VERSION 5.8 ;
BUSBITCHARS "[]" ;
DIVIDERCHAR "/" ;
UNITS
    DATABASE MICRONS 1000 ;
END UNITS

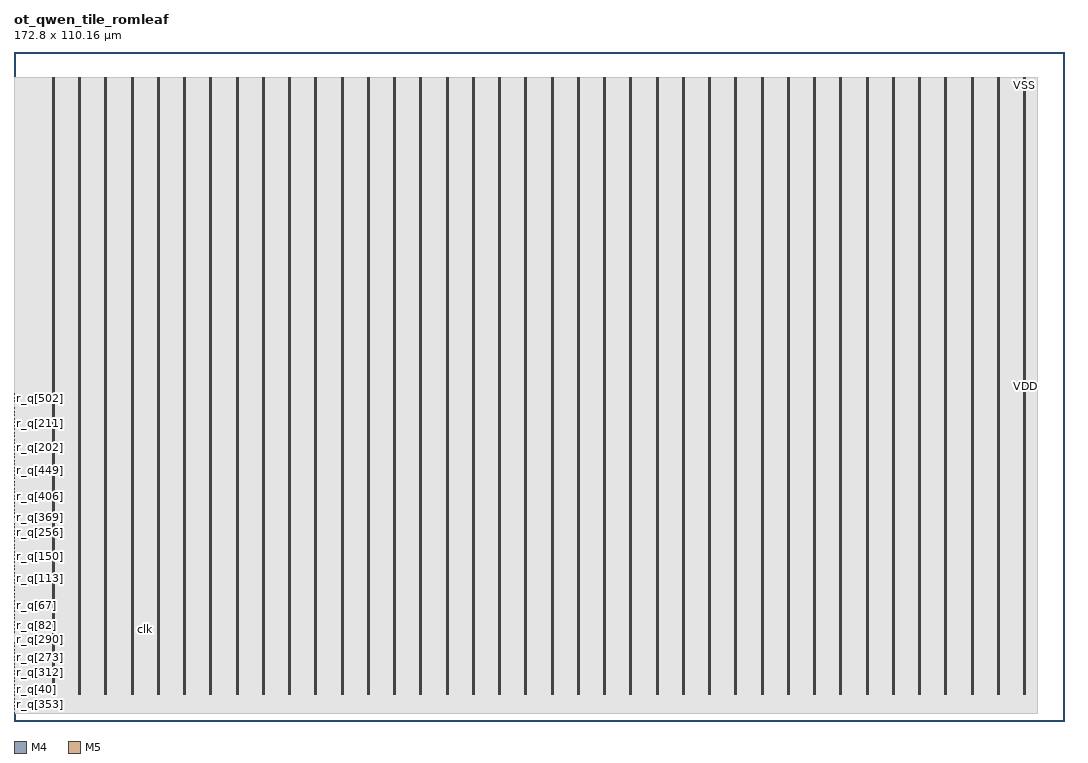
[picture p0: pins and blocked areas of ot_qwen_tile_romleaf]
MACRO ot_qwen_tile_romleaf
  FOREIGN ot_qwen_tile_romleaf 0 0 ;
  CLASS BLOCK ;
  SIZE 172.8 BY 110.16 ;
  PIN ad_d[0]
    DIRECTION INPUT ;
    USE SIGNAL ;
    PORT
      LAYER M4 ;
        RECT  0 20.4 0.084 20.424 ;
    END
  END ad_d[0]
  PIN ad_d[10]
    DIRECTION INPUT ;
    USE SIGNAL ;
    PORT
      LAYER M4 ;
        RECT  0 21.36 0.084 21.384 ;
    END
  END ad_d[10]
  PIN ad_d[11]
    DIRECTION INPUT ;
    USE SIGNAL ;
    PORT
      LAYER M4 ;
        RECT  0 21.456 0.084 21.48 ;
    END
  END ad_d[11]
  PIN ad_d[1]
    DIRECTION INPUT ;
    USE SIGNAL ;
    PORT
      LAYER M4 ;
        RECT  0 20.496 0.084 20.52 ;
    END
  END ad_d[1]
  PIN ad_d[2]
    DIRECTION INPUT ;
    USE SIGNAL ;
    PORT
      LAYER M4 ;
        RECT  0 20.592 0.084 20.616 ;
    END
  END ad_d[2]
  PIN ad_d[3]
    DIRECTION INPUT ;
    USE SIGNAL ;
    PORT
      LAYER M4 ;
        RECT  0 20.688 0.084 20.712 ;
    END
  END ad_d[3]
  PIN ad_d[4]
    DIRECTION INPUT ;
    USE SIGNAL ;
    PORT
      LAYER M4 ;
        RECT  0 20.784 0.084 20.808 ;
    END
  END ad_d[4]
  PIN ad_d[5]
    DIRECTION INPUT ;
    USE SIGNAL ;
    PORT
      LAYER M4 ;
        RECT  0 20.88 0.084 20.904 ;
    END
  END ad_d[5]
  PIN ad_d[6]
    DIRECTION INPUT ;
    USE SIGNAL ;
    PORT
      LAYER M4 ;
        RECT  0 20.976 0.084 21 ;
    END
  END ad_d[6]
  PIN ad_d[7]
    DIRECTION INPUT ;
    USE SIGNAL ;
    PORT
      LAYER M4 ;
        RECT  0 21.072 0.084 21.096 ;
    END
  END ad_d[7]
  PIN ad_d[8]
    DIRECTION INPUT ;
    USE SIGNAL ;
    PORT
      LAYER M4 ;
        RECT  0 21.168 0.084 21.192 ;
    END
  END ad_d[8]
  PIN ad_d[9]
    DIRECTION INPUT ;
    USE SIGNAL ;
    PORT
      LAYER M4 ;
        RECT  0 21.264 0.084 21.288 ;
    END
  END ad_d[9]
  PIN any_d
    DIRECTION INPUT ;
    USE SIGNAL ;
    PORT
      LAYER M4 ;
        RECT  0 21.552 0.084 21.576 ;
    END
  END any_d
  PIN ce_d
    DIRECTION INPUT ;
    USE SIGNAL ;
    PORT
      LAYER M4 ;
        RECT  0 21.648 0.084 21.672 ;
    END
  END ce_d
  PIN clk
    DIRECTION INPUT ;
    USE SIGNAL ;
    PORT
      LAYER M5 ;
        RECT  21.588 14.88 21.636 15.36 ;
    END
  END clk
  PIN r_q[0]
    DIRECTION OUTPUT ;
    USE SIGNAL ;
    PORT
      LAYER M4 ;
        RECT  0 21.84 0.084 21.864 ;
    END
  END r_q[0]
  PIN r_q[100]
    DIRECTION OUTPUT ;
    USE SIGNAL ;
    PORT
      LAYER M4 ;
        RECT  0 16.08 0.084 16.104 ;
    END
  END r_q[100]
  PIN r_q[101]
    DIRECTION OUTPUT ;
    USE SIGNAL ;
    PORT
      LAYER M4 ;
        RECT  0 16.176 0.084 16.2 ;
    END
  END r_q[101]
  PIN r_q[102]
    DIRECTION OUTPUT ;
    USE SIGNAL ;
    PORT
      LAYER M4 ;
        RECT  0 16.272 0.084 16.296 ;
    END
  END r_q[102]
  PIN r_q[103]
    DIRECTION OUTPUT ;
    USE SIGNAL ;
    PORT
      LAYER M4 ;
        RECT  0 16.368 0.084 16.392 ;
    END
  END r_q[103]
  PIN r_q[104]
    DIRECTION OUTPUT ;
    USE SIGNAL ;
    PORT
      LAYER M4 ;
        RECT  0 16.464 0.084 16.488 ;
    END
  END r_q[104]
  PIN r_q[105]
    DIRECTION OUTPUT ;
    USE SIGNAL ;
    PORT
      LAYER M4 ;
        RECT  0 16.56 0.084 16.584 ;
    END
  END r_q[105]
  PIN r_q[106]
    DIRECTION OUTPUT ;
    USE SIGNAL ;
    PORT
      LAYER M4 ;
        RECT  0 16.656 0.084 16.68 ;
    END
  END r_q[106]
  PIN r_q[107]
    DIRECTION OUTPUT ;
    USE SIGNAL ;
    PORT
      LAYER M4 ;
        RECT  0 16.752 0.084 16.776 ;
    END
  END r_q[107]
  PIN r_q[108]
    DIRECTION OUTPUT ;
    USE SIGNAL ;
    PORT
      LAYER M4 ;
        RECT  0 16.848 0.084 16.872 ;
    END
  END r_q[108]
  PIN r_q[109]
    DIRECTION OUTPUT ;
    USE SIGNAL ;
    PORT
      LAYER M4 ;
        RECT  0 16.944 0.084 16.968 ;
    END
  END r_q[109]
  PIN r_q[10]
    DIRECTION OUTPUT ;
    USE SIGNAL ;
    PORT
      LAYER M4 ;
        RECT  0 22.8 0.084 22.824 ;
    END
  END r_q[10]
  PIN r_q[110]
    DIRECTION OUTPUT ;
    USE SIGNAL ;
    PORT
      LAYER M4 ;
        RECT  0 17.04 0.084 17.064 ;
    END
  END r_q[110]
  PIN r_q[111]
    DIRECTION OUTPUT ;
    USE SIGNAL ;
    PORT
      LAYER M4 ;
        RECT  0 17.136 0.084 17.16 ;
    END
  END r_q[111]
  PIN r_q[112]
    DIRECTION OUTPUT ;
    USE SIGNAL ;
    PORT
      LAYER M4 ;
        RECT  0 17.232 0.084 17.256 ;
    END
  END r_q[112]
  PIN r_q[113]
    DIRECTION OUTPUT ;
    USE SIGNAL ;
    PORT
      LAYER M4 ;
        RECT  0 23.472 0.084 23.496 ;
    END
  END r_q[113]
  PIN r_q[114]
    DIRECTION OUTPUT ;
    USE SIGNAL ;
    PORT
      LAYER M4 ;
        RECT  0 23.568 0.084 23.592 ;
    END
  END r_q[114]
  PIN r_q[115]
    DIRECTION OUTPUT ;
    USE SIGNAL ;
    PORT
      LAYER M4 ;
        RECT  0 23.664 0.084 23.688 ;
    END
  END r_q[115]
  PIN r_q[116]
    DIRECTION OUTPUT ;
    USE SIGNAL ;
    PORT
      LAYER M4 ;
        RECT  0 23.76 0.084 23.784 ;
    END
  END r_q[116]
  PIN r_q[117]
    DIRECTION OUTPUT ;
    USE SIGNAL ;
    PORT
      LAYER M4 ;
        RECT  0 23.856 0.084 23.88 ;
    END
  END r_q[117]
  PIN r_q[118]
    DIRECTION OUTPUT ;
    USE SIGNAL ;
    PORT
      LAYER M4 ;
        RECT  0 23.952 0.084 23.976 ;
    END
  END r_q[118]
  PIN r_q[119]
    DIRECTION OUTPUT ;
    USE SIGNAL ;
    PORT
      LAYER M4 ;
        RECT  0 24.048 0.084 24.072 ;
    END
  END r_q[119]
  PIN r_q[11]
    DIRECTION OUTPUT ;
    USE SIGNAL ;
    PORT
      LAYER M4 ;
        RECT  0 22.896 0.084 22.92 ;
    END
  END r_q[11]
  PIN r_q[120]
    DIRECTION OUTPUT ;
    USE SIGNAL ;
    PORT
      LAYER M4 ;
        RECT  0 24.144 0.084 24.168 ;
    END
  END r_q[120]
  PIN r_q[121]
    DIRECTION OUTPUT ;
    USE SIGNAL ;
    PORT
      LAYER M4 ;
        RECT  0 24.24 0.084 24.264 ;
    END
  END r_q[121]
  PIN r_q[122]
    DIRECTION OUTPUT ;
    USE SIGNAL ;
    PORT
      LAYER M4 ;
        RECT  0 24.336 0.084 24.36 ;
    END
  END r_q[122]
  PIN r_q[123]
    DIRECTION OUTPUT ;
    USE SIGNAL ;
    PORT
      LAYER M4 ;
        RECT  0 24.432 0.084 24.456 ;
    END
  END r_q[123]
  PIN r_q[124]
    DIRECTION OUTPUT ;
    USE SIGNAL ;
    PORT
      LAYER M4 ;
        RECT  0 24.528 0.084 24.552 ;
    END
  END r_q[124]
  PIN r_q[125]
    DIRECTION OUTPUT ;
    USE SIGNAL ;
    PORT
      LAYER M4 ;
        RECT  0 24.624 0.084 24.648 ;
    END
  END r_q[125]
  PIN r_q[126]
    DIRECTION OUTPUT ;
    USE SIGNAL ;
    PORT
      LAYER M4 ;
        RECT  0 24.72 0.084 24.744 ;
    END
  END r_q[126]
  PIN r_q[127]
    DIRECTION OUTPUT ;
    USE SIGNAL ;
    PORT
      LAYER M4 ;
        RECT  0 24.816 0.084 24.84 ;
    END
  END r_q[127]
  PIN r_q[128]
    DIRECTION OUTPUT ;
    USE SIGNAL ;
    PORT
      LAYER M4 ;
        RECT  0 24.912 0.084 24.936 ;
    END
  END r_q[128]
  PIN r_q[129]
    DIRECTION OUTPUT ;
    USE SIGNAL ;
    PORT
      LAYER M4 ;
        RECT  0 25.008 0.084 25.032 ;
    END
  END r_q[129]
  PIN r_q[12]
    DIRECTION OUTPUT ;
    USE SIGNAL ;
    PORT
      LAYER M4 ;
        RECT  0 22.992 0.084 23.016 ;
    END
  END r_q[12]
  PIN r_q[130]
    DIRECTION OUTPUT ;
    USE SIGNAL ;
    PORT
      LAYER M4 ;
        RECT  0 25.104 0.084 25.128 ;
    END
  END r_q[130]
  PIN r_q[131]
    DIRECTION OUTPUT ;
    USE SIGNAL ;
    PORT
      LAYER M4 ;
        RECT  0 25.2 0.084 25.224 ;
    END
  END r_q[131]
  PIN r_q[132]
    DIRECTION OUTPUT ;
    USE SIGNAL ;
    PORT
      LAYER M4 ;
        RECT  0 25.296 0.084 25.32 ;
    END
  END r_q[132]
  PIN r_q[133]
    DIRECTION OUTPUT ;
    USE SIGNAL ;
    PORT
      LAYER M4 ;
        RECT  0 25.392 0.084 25.416 ;
    END
  END r_q[133]
  PIN r_q[134]
    DIRECTION OUTPUT ;
    USE SIGNAL ;
    PORT
      LAYER M4 ;
        RECT  0 25.488 0.084 25.512 ;
    END
  END r_q[134]
  PIN r_q[135]
    DIRECTION OUTPUT ;
    USE SIGNAL ;
    PORT
      LAYER M4 ;
        RECT  0 25.584 0.084 25.608 ;
    END
  END r_q[135]
  PIN r_q[136]
    DIRECTION OUTPUT ;
    USE SIGNAL ;
    PORT
      LAYER M4 ;
        RECT  0 25.68 0.084 25.704 ;
    END
  END r_q[136]
  PIN r_q[137]
    DIRECTION OUTPUT ;
    USE SIGNAL ;
    PORT
      LAYER M4 ;
        RECT  0 25.776 0.084 25.8 ;
    END
  END r_q[137]
  PIN r_q[138]
    DIRECTION OUTPUT ;
    USE SIGNAL ;
    PORT
      LAYER M4 ;
        RECT  0 25.872 0.084 25.896 ;
    END
  END r_q[138]
  PIN r_q[139]
    DIRECTION OUTPUT ;
    USE SIGNAL ;
    PORT
      LAYER M4 ;
        RECT  0 25.968 0.084 25.992 ;
    END
  END r_q[139]
  PIN r_q[13]
    DIRECTION OUTPUT ;
    USE SIGNAL ;
    PORT
      LAYER M4 ;
        RECT  0 23.088 0.084 23.112 ;
    END
  END r_q[13]
  PIN r_q[140]
    DIRECTION OUTPUT ;
    USE SIGNAL ;
    PORT
      LAYER M4 ;
        RECT  0 26.064 0.084 26.088 ;
    END
  END r_q[140]
  PIN r_q[141]
    DIRECTION OUTPUT ;
    USE SIGNAL ;
    PORT
      LAYER M4 ;
        RECT  0 26.16 0.084 26.184 ;
    END
  END r_q[141]
  PIN r_q[142]
    DIRECTION OUTPUT ;
    USE SIGNAL ;
    PORT
      LAYER M4 ;
        RECT  0 26.256 0.084 26.28 ;
    END
  END r_q[142]
  PIN r_q[143]
    DIRECTION OUTPUT ;
    USE SIGNAL ;
    PORT
      LAYER M4 ;
        RECT  0 26.352 0.084 26.376 ;
    END
  END r_q[143]
  PIN r_q[144]
    DIRECTION OUTPUT ;
    USE SIGNAL ;
    PORT
      LAYER M4 ;
        RECT  0 26.448 0.084 26.472 ;
    END
  END r_q[144]
  PIN r_q[145]
    DIRECTION OUTPUT ;
    USE SIGNAL ;
    PORT
      LAYER M4 ;
        RECT  0 26.544 0.084 26.568 ;
    END
  END r_q[145]
  PIN r_q[146]
    DIRECTION OUTPUT ;
    USE SIGNAL ;
    PORT
      LAYER M4 ;
        RECT  0 26.64 0.084 26.664 ;
    END
  END r_q[146]
  PIN r_q[147]
    DIRECTION OUTPUT ;
    USE SIGNAL ;
    PORT
      LAYER M4 ;
        RECT  0 26.736 0.084 26.76 ;
    END
  END r_q[147]
  PIN r_q[148]
    DIRECTION OUTPUT ;
    USE SIGNAL ;
    PORT
      LAYER M4 ;
        RECT  0 26.832 0.084 26.856 ;
    END
  END r_q[148]
  PIN r_q[149]
    DIRECTION OUTPUT ;
    USE SIGNAL ;
    PORT
      LAYER M4 ;
        RECT  0 26.928 0.084 26.952 ;
    END
  END r_q[149]
  PIN r_q[14]
    DIRECTION OUTPUT ;
    USE SIGNAL ;
    PORT
      LAYER M4 ;
        RECT  0 23.184 0.084 23.208 ;
    END
  END r_q[14]
  PIN r_q[150]
    DIRECTION OUTPUT ;
    USE SIGNAL ;
    PORT
      LAYER M4 ;
        RECT  0 27.024 0.084 27.048 ;
    END
  END r_q[150]
  PIN r_q[151]
    DIRECTION OUTPUT ;
    USE SIGNAL ;
    PORT
      LAYER M4 ;
        RECT  0 27.12 0.084 27.144 ;
    END
  END r_q[151]
  PIN r_q[152]
    DIRECTION OUTPUT ;
    USE SIGNAL ;
    PORT
      LAYER M4 ;
        RECT  0 27.216 0.084 27.24 ;
    END
  END r_q[152]
  PIN r_q[153]
    DIRECTION OUTPUT ;
    USE SIGNAL ;
    PORT
      LAYER M4 ;
        RECT  0 27.312 0.084 27.336 ;
    END
  END r_q[153]
  PIN r_q[154]
    DIRECTION OUTPUT ;
    USE SIGNAL ;
    PORT
      LAYER M4 ;
        RECT  0 27.408 0.084 27.432 ;
    END
  END r_q[154]
  PIN r_q[155]
    DIRECTION OUTPUT ;
    USE SIGNAL ;
    PORT
      LAYER M4 ;
        RECT  0 27.504 0.084 27.528 ;
    END
  END r_q[155]
  PIN r_q[156]
    DIRECTION OUTPUT ;
    USE SIGNAL ;
    PORT
      LAYER M4 ;
        RECT  0 27.6 0.084 27.624 ;
    END
  END r_q[156]
  PIN r_q[157]
    DIRECTION OUTPUT ;
    USE SIGNAL ;
    PORT
      LAYER M4 ;
        RECT  0 27.696 0.084 27.72 ;
    END
  END r_q[157]
  PIN r_q[158]
    DIRECTION OUTPUT ;
    USE SIGNAL ;
    PORT
      LAYER M4 ;
        RECT  0 27.792 0.084 27.816 ;
    END
  END r_q[158]
  PIN r_q[159]
    DIRECTION OUTPUT ;
    USE SIGNAL ;
    PORT
      LAYER M4 ;
        RECT  0 27.888 0.084 27.912 ;
    END
  END r_q[159]
  PIN r_q[15]
    DIRECTION OUTPUT ;
    USE SIGNAL ;
    PORT
      LAYER M4 ;
        RECT  0 23.28 0.084 23.304 ;
    END
  END r_q[15]
  PIN r_q[160]
    DIRECTION OUTPUT ;
    USE SIGNAL ;
    PORT
      LAYER M4 ;
        RECT  0 27.984 0.084 28.008 ;
    END
  END r_q[160]
  PIN r_q[161]
    DIRECTION OUTPUT ;
    USE SIGNAL ;
    PORT
      LAYER M4 ;
        RECT  0 28.08 0.084 28.104 ;
    END
  END r_q[161]
  PIN r_q[162]
    DIRECTION OUTPUT ;
    USE SIGNAL ;
    PORT
      LAYER M4 ;
        RECT  0 28.176 0.084 28.2 ;
    END
  END r_q[162]
  PIN r_q[163]
    DIRECTION OUTPUT ;
    USE SIGNAL ;
    PORT
      LAYER M4 ;
        RECT  0 28.272 0.084 28.296 ;
    END
  END r_q[163]
  PIN r_q[164]
    DIRECTION OUTPUT ;
    USE SIGNAL ;
    PORT
      LAYER M4 ;
        RECT  0 28.368 0.084 28.392 ;
    END
  END r_q[164]
  PIN r_q[165]
    DIRECTION OUTPUT ;
    USE SIGNAL ;
    PORT
      LAYER M4 ;
        RECT  0 28.464 0.084 28.488 ;
    END
  END r_q[165]
  PIN r_q[166]
    DIRECTION OUTPUT ;
    USE SIGNAL ;
    PORT
      LAYER M4 ;
        RECT  0 28.56 0.084 28.584 ;
    END
  END r_q[166]
  PIN r_q[167]
    DIRECTION OUTPUT ;
    USE SIGNAL ;
    PORT
      LAYER M4 ;
        RECT  0 28.656 0.084 28.68 ;
    END
  END r_q[167]
  PIN r_q[168]
    DIRECTION OUTPUT ;
    USE SIGNAL ;
    PORT
      LAYER M4 ;
        RECT  0 28.752 0.084 28.776 ;
    END
  END r_q[168]
  PIN r_q[169]
    DIRECTION OUTPUT ;
    USE SIGNAL ;
    PORT
      LAYER M4 ;
        RECT  0 28.848 0.084 28.872 ;
    END
  END r_q[169]
  PIN r_q[16]
    DIRECTION OUTPUT ;
    USE SIGNAL ;
    PORT
      LAYER M4 ;
        RECT  0 23.376 0.084 23.4 ;
    END
  END r_q[16]
  PIN r_q[170]
    DIRECTION OUTPUT ;
    USE SIGNAL ;
    PORT
      LAYER M4 ;
        RECT  0 28.944 0.084 28.968 ;
    END
  END r_q[170]
  PIN r_q[171]
    DIRECTION OUTPUT ;
    USE SIGNAL ;
    PORT
      LAYER M4 ;
        RECT  0 29.04 0.084 29.064 ;
    END
  END r_q[171]
  PIN r_q[172]
    DIRECTION OUTPUT ;
    USE SIGNAL ;
    PORT
      LAYER M4 ;
        RECT  0 29.136 0.084 29.16 ;
    END
  END r_q[172]
  PIN r_q[173]
    DIRECTION OUTPUT ;
    USE SIGNAL ;
    PORT
      LAYER M4 ;
        RECT  0 29.232 0.084 29.256 ;
    END
  END r_q[173]
  PIN r_q[174]
    DIRECTION OUTPUT ;
    USE SIGNAL ;
    PORT
      LAYER M4 ;
        RECT  0 29.328 0.084 29.352 ;
    END
  END r_q[174]
  PIN r_q[175]
    DIRECTION OUTPUT ;
    USE SIGNAL ;
    PORT
      LAYER M4 ;
        RECT  0 29.424 0.084 29.448 ;
    END
  END r_q[175]
  PIN r_q[176]
    DIRECTION OUTPUT ;
    USE SIGNAL ;
    PORT
      LAYER M4 ;
        RECT  0 29.52 0.084 29.544 ;
    END
  END r_q[176]
  PIN r_q[177]
    DIRECTION OUTPUT ;
    USE SIGNAL ;
    PORT
      LAYER M4 ;
        RECT  0 42.672 0.084 42.696 ;
    END
  END r_q[177]
  PIN r_q[178]
    DIRECTION OUTPUT ;
    USE SIGNAL ;
    PORT
      LAYER M4 ;
        RECT  0 42.768 0.084 42.792 ;
    END
  END r_q[178]
  PIN r_q[179]
    DIRECTION OUTPUT ;
    USE SIGNAL ;
    PORT
      LAYER M4 ;
        RECT  0 42.864 0.084 42.888 ;
    END
  END r_q[179]
  PIN r_q[17]
    DIRECTION OUTPUT ;
    USE SIGNAL ;
    PORT
      LAYER M4 ;
        RECT  0 4.272 0.084 4.296 ;
    END
  END r_q[17]
  PIN r_q[180]
    DIRECTION OUTPUT ;
    USE SIGNAL ;
    PORT
      LAYER M4 ;
        RECT  0 42.96 0.084 42.984 ;
    END
  END r_q[180]
  PIN r_q[181]
    DIRECTION OUTPUT ;
    USE SIGNAL ;
    PORT
      LAYER M4 ;
        RECT  0 43.056 0.084 43.08 ;
    END
  END r_q[181]
  PIN r_q[182]
    DIRECTION OUTPUT ;
    USE SIGNAL ;
    PORT
      LAYER M4 ;
        RECT  0 43.152 0.084 43.176 ;
    END
  END r_q[182]
  PIN r_q[183]
    DIRECTION OUTPUT ;
    USE SIGNAL ;
    PORT
      LAYER M4 ;
        RECT  0 43.248 0.084 43.272 ;
    END
  END r_q[183]
  PIN r_q[184]
    DIRECTION OUTPUT ;
    USE SIGNAL ;
    PORT
      LAYER M4 ;
        RECT  0 43.344 0.084 43.368 ;
    END
  END r_q[184]
  PIN r_q[185]
    DIRECTION OUTPUT ;
    USE SIGNAL ;
    PORT
      LAYER M4 ;
        RECT  0 43.44 0.084 43.464 ;
    END
  END r_q[185]
  PIN r_q[186]
    DIRECTION OUTPUT ;
    USE SIGNAL ;
    PORT
      LAYER M4 ;
        RECT  0 43.536 0.084 43.56 ;
    END
  END r_q[186]
  PIN r_q[187]
    DIRECTION OUTPUT ;
    USE SIGNAL ;
    PORT
      LAYER M4 ;
        RECT  0 43.632 0.084 43.656 ;
    END
  END r_q[187]
  PIN r_q[188]
    DIRECTION OUTPUT ;
    USE SIGNAL ;
    PORT
      LAYER M4 ;
        RECT  0 43.728 0.084 43.752 ;
    END
  END r_q[188]
  PIN r_q[189]
    DIRECTION OUTPUT ;
    USE SIGNAL ;
    PORT
      LAYER M4 ;
        RECT  0 43.824 0.084 43.848 ;
    END
  END r_q[189]
  PIN r_q[18]
    DIRECTION OUTPUT ;
    USE SIGNAL ;
    PORT
      LAYER M4 ;
        RECT  0 4.368 0.084 4.392 ;
    END
  END r_q[18]
  PIN r_q[190]
    DIRECTION OUTPUT ;
    USE SIGNAL ;
    PORT
      LAYER M4 ;
        RECT  0 43.92 0.084 43.944 ;
    END
  END r_q[190]
  PIN r_q[191]
    DIRECTION OUTPUT ;
    USE SIGNAL ;
    PORT
      LAYER M4 ;
        RECT  0 44.016 0.084 44.04 ;
    END
  END r_q[191]
  PIN r_q[192]
    DIRECTION OUTPUT ;
    USE SIGNAL ;
    PORT
      LAYER M4 ;
        RECT  0 44.112 0.084 44.136 ;
    END
  END r_q[192]
  PIN r_q[193]
    DIRECTION OUTPUT ;
    USE SIGNAL ;
    PORT
      LAYER M4 ;
        RECT  0 44.208 0.084 44.232 ;
    END
  END r_q[193]
  PIN r_q[194]
    DIRECTION OUTPUT ;
    USE SIGNAL ;
    PORT
      LAYER M4 ;
        RECT  0 44.304 0.084 44.328 ;
    END
  END r_q[194]
  PIN r_q[195]
    DIRECTION OUTPUT ;
    USE SIGNAL ;
    PORT
      LAYER M4 ;
        RECT  0 44.4 0.084 44.424 ;
    END
  END r_q[195]
  PIN r_q[196]
    DIRECTION OUTPUT ;
    USE SIGNAL ;
    PORT
      LAYER M4 ;
        RECT  0 44.496 0.084 44.52 ;
    END
  END r_q[196]
  PIN r_q[197]
    DIRECTION OUTPUT ;
    USE SIGNAL ;
    PORT
      LAYER M4 ;
        RECT  0 44.592 0.084 44.616 ;
    END
  END r_q[197]
  PIN r_q[198]
    DIRECTION OUTPUT ;
    USE SIGNAL ;
    PORT
      LAYER M4 ;
        RECT  0 44.688 0.084 44.712 ;
    END
  END r_q[198]
  PIN r_q[199]
    DIRECTION OUTPUT ;
    USE SIGNAL ;
    PORT
      LAYER M4 ;
        RECT  0 44.784 0.084 44.808 ;
    END
  END r_q[199]
  PIN r_q[19]
    DIRECTION OUTPUT ;
    USE SIGNAL ;
    PORT
      LAYER M4 ;
        RECT  0 4.464 0.084 4.488 ;
    END
  END r_q[19]
  PIN r_q[1]
    DIRECTION OUTPUT ;
    USE SIGNAL ;
    PORT
      LAYER M4 ;
        RECT  0 21.936 0.084 21.96 ;
    END
  END r_q[1]
  PIN r_q[200]
    DIRECTION OUTPUT ;
    USE SIGNAL ;
    PORT
      LAYER M4 ;
        RECT  0 44.88 0.084 44.904 ;
    END
  END r_q[200]
  PIN r_q[201]
    DIRECTION OUTPUT ;
    USE SIGNAL ;
    PORT
      LAYER M4 ;
        RECT  0 44.976 0.084 45 ;
    END
  END r_q[201]
  PIN r_q[202]
    DIRECTION OUTPUT ;
    USE SIGNAL ;
    PORT
      LAYER M4 ;
        RECT  0 45.072 0.084 45.096 ;
    END
  END r_q[202]
  PIN r_q[203]
    DIRECTION OUTPUT ;
    USE SIGNAL ;
    PORT
      LAYER M4 ;
        RECT  0 45.168 0.084 45.192 ;
    END
  END r_q[203]
  PIN r_q[204]
    DIRECTION OUTPUT ;
    USE SIGNAL ;
    PORT
      LAYER M4 ;
        RECT  0 45.264 0.084 45.288 ;
    END
  END r_q[204]
  PIN r_q[205]
    DIRECTION OUTPUT ;
    USE SIGNAL ;
    PORT
      LAYER M4 ;
        RECT  0 45.36 0.084 45.384 ;
    END
  END r_q[205]
  PIN r_q[206]
    DIRECTION OUTPUT ;
    USE SIGNAL ;
    PORT
      LAYER M4 ;
        RECT  0 45.456 0.084 45.48 ;
    END
  END r_q[206]
  PIN r_q[207]
    DIRECTION OUTPUT ;
    USE SIGNAL ;
    PORT
      LAYER M4 ;
        RECT  0 45.552 0.084 45.576 ;
    END
  END r_q[207]
  PIN r_q[208]
    DIRECTION OUTPUT ;
    USE SIGNAL ;
    PORT
      LAYER M4 ;
        RECT  0 45.648 0.084 45.672 ;
    END
  END r_q[208]
  PIN r_q[209]
    DIRECTION OUTPUT ;
    USE SIGNAL ;
    PORT
      LAYER M4 ;
        RECT  0 48.816 0.084 48.84 ;
    END
  END r_q[209]
  PIN r_q[20]
    DIRECTION OUTPUT ;
    USE SIGNAL ;
    PORT
      LAYER M4 ;
        RECT  0 4.56 0.084 4.584 ;
    END
  END r_q[20]
  PIN r_q[210]
    DIRECTION OUTPUT ;
    USE SIGNAL ;
    PORT
      LAYER M4 ;
        RECT  0 48.912 0.084 48.936 ;
    END
  END r_q[210]
  PIN r_q[211]
    DIRECTION OUTPUT ;
    USE SIGNAL ;
    PORT
      LAYER M4 ;
        RECT  0 49.008 0.084 49.032 ;
    END
  END r_q[211]
  PIN r_q[212]
    DIRECTION OUTPUT ;
    USE SIGNAL ;
    PORT
      LAYER M4 ;
        RECT  0 49.104 0.084 49.128 ;
    END
  END r_q[212]
  PIN r_q[213]
    DIRECTION OUTPUT ;
    USE SIGNAL ;
    PORT
      LAYER M4 ;
        RECT  0 49.2 0.084 49.224 ;
    END
  END r_q[213]
  PIN r_q[214]
    DIRECTION OUTPUT ;
    USE SIGNAL ;
    PORT
      LAYER M4 ;
        RECT  0 49.296 0.084 49.32 ;
    END
  END r_q[214]
  PIN r_q[215]
    DIRECTION OUTPUT ;
    USE SIGNAL ;
    PORT
      LAYER M4 ;
        RECT  0 49.392 0.084 49.416 ;
    END
  END r_q[215]
  PIN r_q[216]
    DIRECTION OUTPUT ;
    USE SIGNAL ;
    PORT
      LAYER M4 ;
        RECT  0 49.488 0.084 49.512 ;
    END
  END r_q[216]
  PIN r_q[217]
    DIRECTION OUTPUT ;
    USE SIGNAL ;
    PORT
      LAYER M4 ;
        RECT  0 49.584 0.084 49.608 ;
    END
  END r_q[217]
  PIN r_q[218]
    DIRECTION OUTPUT ;
    USE SIGNAL ;
    PORT
      LAYER M4 ;
        RECT  0 49.68 0.084 49.704 ;
    END
  END r_q[218]
  PIN r_q[219]
    DIRECTION OUTPUT ;
    USE SIGNAL ;
    PORT
      LAYER M4 ;
        RECT  0 49.776 0.084 49.8 ;
    END
  END r_q[219]
  PIN r_q[21]
    DIRECTION OUTPUT ;
    USE SIGNAL ;
    PORT
      LAYER M4 ;
        RECT  0 4.656 0.084 4.68 ;
    END
  END r_q[21]
  PIN r_q[220]
    DIRECTION OUTPUT ;
    USE SIGNAL ;
    PORT
      LAYER M4 ;
        RECT  0 49.872 0.084 49.896 ;
    END
  END r_q[220]
  PIN r_q[221]
    DIRECTION OUTPUT ;
    USE SIGNAL ;
    PORT
      LAYER M4 ;
        RECT  0 49.968 0.084 49.992 ;
    END
  END r_q[221]
  PIN r_q[222]
    DIRECTION OUTPUT ;
    USE SIGNAL ;
    PORT
      LAYER M4 ;
        RECT  0 50.064 0.084 50.088 ;
    END
  END r_q[222]
  PIN r_q[223]
    DIRECTION OUTPUT ;
    USE SIGNAL ;
    PORT
      LAYER M4 ;
        RECT  0 50.16 0.084 50.184 ;
    END
  END r_q[223]
  PIN r_q[224]
    DIRECTION OUTPUT ;
    USE SIGNAL ;
    PORT
      LAYER M4 ;
        RECT  0 50.256 0.084 50.28 ;
    END
  END r_q[224]
  PIN r_q[225]
    DIRECTION OUTPUT ;
    USE SIGNAL ;
    PORT
      LAYER M4 ;
        RECT  0 50.352 0.084 50.376 ;
    END
  END r_q[225]
  PIN r_q[226]
    DIRECTION OUTPUT ;
    USE SIGNAL ;
    PORT
      LAYER M4 ;
        RECT  0 50.448 0.084 50.472 ;
    END
  END r_q[226]
  PIN r_q[227]
    DIRECTION OUTPUT ;
    USE SIGNAL ;
    PORT
      LAYER M4 ;
        RECT  0 50.544 0.084 50.568 ;
    END
  END r_q[227]
  PIN r_q[228]
    DIRECTION OUTPUT ;
    USE SIGNAL ;
    PORT
      LAYER M4 ;
        RECT  0 50.64 0.084 50.664 ;
    END
  END r_q[228]
  PIN r_q[229]
    DIRECTION OUTPUT ;
    USE SIGNAL ;
    PORT
      LAYER M4 ;
        RECT  0 50.736 0.084 50.76 ;
    END
  END r_q[229]
  PIN r_q[22]
    DIRECTION OUTPUT ;
    USE SIGNAL ;
    PORT
      LAYER M4 ;
        RECT  0 4.752 0.084 4.776 ;
    END
  END r_q[22]
  PIN r_q[230]
    DIRECTION OUTPUT ;
    USE SIGNAL ;
    PORT
      LAYER M4 ;
        RECT  0 50.832 0.084 50.856 ;
    END
  END r_q[230]
  PIN r_q[231]
    DIRECTION OUTPUT ;
    USE SIGNAL ;
    PORT
      LAYER M4 ;
        RECT  0 50.928 0.084 50.952 ;
    END
  END r_q[231]
  PIN r_q[232]
    DIRECTION OUTPUT ;
    USE SIGNAL ;
    PORT
      LAYER M4 ;
        RECT  0 51.024 0.084 51.048 ;
    END
  END r_q[232]
  PIN r_q[233]
    DIRECTION OUTPUT ;
    USE SIGNAL ;
    PORT
      LAYER M4 ;
        RECT  0 51.12 0.084 51.144 ;
    END
  END r_q[233]
  PIN r_q[234]
    DIRECTION OUTPUT ;
    USE SIGNAL ;
    PORT
      LAYER M4 ;
        RECT  0 51.216 0.084 51.24 ;
    END
  END r_q[234]
  PIN r_q[235]
    DIRECTION OUTPUT ;
    USE SIGNAL ;
    PORT
      LAYER M4 ;
        RECT  0 51.312 0.084 51.336 ;
    END
  END r_q[235]
  PIN r_q[236]
    DIRECTION OUTPUT ;
    USE SIGNAL ;
    PORT
      LAYER M4 ;
        RECT  0 51.408 0.084 51.432 ;
    END
  END r_q[236]
  PIN r_q[237]
    DIRECTION OUTPUT ;
    USE SIGNAL ;
    PORT
      LAYER M4 ;
        RECT  0 51.504 0.084 51.528 ;
    END
  END r_q[237]
  PIN r_q[238]
    DIRECTION OUTPUT ;
    USE SIGNAL ;
    PORT
      LAYER M4 ;
        RECT  0 51.6 0.084 51.624 ;
    END
  END r_q[238]
  PIN r_q[239]
    DIRECTION OUTPUT ;
    USE SIGNAL ;
    PORT
      LAYER M4 ;
        RECT  0 51.696 0.084 51.72 ;
    END
  END r_q[239]
  PIN r_q[23]
    DIRECTION OUTPUT ;
    USE SIGNAL ;
    PORT
      LAYER M4 ;
        RECT  0 4.848 0.084 4.872 ;
    END
  END r_q[23]
  PIN r_q[240]
    DIRECTION OUTPUT ;
    USE SIGNAL ;
    PORT
      LAYER M4 ;
        RECT  0 51.792 0.084 51.816 ;
    END
  END r_q[240]
  PIN r_q[241]
    DIRECTION OUTPUT ;
    USE SIGNAL ;
    PORT
      LAYER M4 ;
        RECT  0 29.616 0.084 29.64 ;
    END
  END r_q[241]
  PIN r_q[242]
    DIRECTION OUTPUT ;
    USE SIGNAL ;
    PORT
      LAYER M4 ;
        RECT  0 29.712 0.084 29.736 ;
    END
  END r_q[242]
  PIN r_q[243]
    DIRECTION OUTPUT ;
    USE SIGNAL ;
    PORT
      LAYER M4 ;
        RECT  0 29.808 0.084 29.832 ;
    END
  END r_q[243]
  PIN r_q[244]
    DIRECTION OUTPUT ;
    USE SIGNAL ;
    PORT
      LAYER M4 ;
        RECT  0 29.904 0.084 29.928 ;
    END
  END r_q[244]
  PIN r_q[245]
    DIRECTION OUTPUT ;
    USE SIGNAL ;
    PORT
      LAYER M4 ;
        RECT  0 30 0.084 30.024 ;
    END
  END r_q[245]
  PIN r_q[246]
    DIRECTION OUTPUT ;
    USE SIGNAL ;
    PORT
      LAYER M4 ;
        RECT  0 30.096 0.084 30.12 ;
    END
  END r_q[246]
  PIN r_q[247]
    DIRECTION OUTPUT ;
    USE SIGNAL ;
    PORT
      LAYER M4 ;
        RECT  0 30.192 0.084 30.216 ;
    END
  END r_q[247]
  PIN r_q[248]
    DIRECTION OUTPUT ;
    USE SIGNAL ;
    PORT
      LAYER M4 ;
        RECT  0 30.288 0.084 30.312 ;
    END
  END r_q[248]
  PIN r_q[249]
    DIRECTION OUTPUT ;
    USE SIGNAL ;
    PORT
      LAYER M4 ;
        RECT  0 30.384 0.084 30.408 ;
    END
  END r_q[249]
  PIN r_q[24]
    DIRECTION OUTPUT ;
    USE SIGNAL ;
    PORT
      LAYER M4 ;
        RECT  0 4.944 0.084 4.968 ;
    END
  END r_q[24]
  PIN r_q[250]
    DIRECTION OUTPUT ;
    USE SIGNAL ;
    PORT
      LAYER M4 ;
        RECT  0 30.48 0.084 30.504 ;
    END
  END r_q[250]
  PIN r_q[251]
    DIRECTION OUTPUT ;
    USE SIGNAL ;
    PORT
      LAYER M4 ;
        RECT  0 30.576 0.084 30.6 ;
    END
  END r_q[251]
  PIN r_q[252]
    DIRECTION OUTPUT ;
    USE SIGNAL ;
    PORT
      LAYER M4 ;
        RECT  0 30.672 0.084 30.696 ;
    END
  END r_q[252]
  PIN r_q[253]
    DIRECTION OUTPUT ;
    USE SIGNAL ;
    PORT
      LAYER M4 ;
        RECT  0 30.768 0.084 30.792 ;
    END
  END r_q[253]
  PIN r_q[254]
    DIRECTION OUTPUT ;
    USE SIGNAL ;
    PORT
      LAYER M4 ;
        RECT  0 30.864 0.084 30.888 ;
    END
  END r_q[254]
  PIN r_q[255]
    DIRECTION OUTPUT ;
    USE SIGNAL ;
    PORT
      LAYER M4 ;
        RECT  0 30.96 0.084 30.984 ;
    END
  END r_q[255]
  PIN r_q[256]
    DIRECTION OUTPUT ;
    USE SIGNAL ;
    PORT
      LAYER M4 ;
        RECT  0 31.056 0.084 31.08 ;
    END
  END r_q[256]
  PIN r_q[257]
    DIRECTION OUTPUT ;
    USE SIGNAL ;
    PORT
      LAYER M4 ;
        RECT  0 31.152 0.084 31.176 ;
    END
  END r_q[257]
  PIN r_q[258]
    DIRECTION OUTPUT ;
    USE SIGNAL ;
    PORT
      LAYER M4 ;
        RECT  0 31.248 0.084 31.272 ;
    END
  END r_q[258]
  PIN r_q[259]
    DIRECTION OUTPUT ;
    USE SIGNAL ;
    PORT
      LAYER M4 ;
        RECT  0 31.344 0.084 31.368 ;
    END
  END r_q[259]
  PIN r_q[25]
    DIRECTION OUTPUT ;
    USE SIGNAL ;
    PORT
      LAYER M4 ;
        RECT  0 5.04 0.084 5.064 ;
    END
  END r_q[25]
  PIN r_q[260]
    DIRECTION OUTPUT ;
    USE SIGNAL ;
    PORT
      LAYER M4 ;
        RECT  0 31.44 0.084 31.464 ;
    END
  END r_q[260]
  PIN r_q[261]
    DIRECTION OUTPUT ;
    USE SIGNAL ;
    PORT
      LAYER M4 ;
        RECT  0 31.536 0.084 31.56 ;
    END
  END r_q[261]
  PIN r_q[262]
    DIRECTION OUTPUT ;
    USE SIGNAL ;
    PORT
      LAYER M4 ;
        RECT  0 31.632 0.084 31.656 ;
    END
  END r_q[262]
  PIN r_q[263]
    DIRECTION OUTPUT ;
    USE SIGNAL ;
    PORT
      LAYER M4 ;
        RECT  0 31.728 0.084 31.752 ;
    END
  END r_q[263]
  PIN r_q[264]
    DIRECTION OUTPUT ;
    USE SIGNAL ;
    PORT
      LAYER M4 ;
        RECT  0 31.824 0.084 31.848 ;
    END
  END r_q[264]
  PIN r_q[265]
    DIRECTION OUTPUT ;
    USE SIGNAL ;
    PORT
      LAYER M4 ;
        RECT  0 31.92 0.084 31.944 ;
    END
  END r_q[265]
  PIN r_q[266]
    DIRECTION OUTPUT ;
    USE SIGNAL ;
    PORT
      LAYER M4 ;
        RECT  0 32.016 0.084 32.04 ;
    END
  END r_q[266]
  PIN r_q[267]
    DIRECTION OUTPUT ;
    USE SIGNAL ;
    PORT
      LAYER M4 ;
        RECT  0 32.112 0.084 32.136 ;
    END
  END r_q[267]
  PIN r_q[268]
    DIRECTION OUTPUT ;
    USE SIGNAL ;
    PORT
      LAYER M4 ;
        RECT  0 32.208 0.084 32.232 ;
    END
  END r_q[268]
  PIN r_q[269]
    DIRECTION OUTPUT ;
    USE SIGNAL ;
    PORT
      LAYER M4 ;
        RECT  0 32.304 0.084 32.328 ;
    END
  END r_q[269]
  PIN r_q[26]
    DIRECTION OUTPUT ;
    USE SIGNAL ;
    PORT
      LAYER M4 ;
        RECT  0 5.136 0.084 5.16 ;
    END
  END r_q[26]
  PIN r_q[270]
    DIRECTION OUTPUT ;
    USE SIGNAL ;
    PORT
      LAYER M4 ;
        RECT  0 32.4 0.084 32.424 ;
    END
  END r_q[270]
  PIN r_q[271]
    DIRECTION OUTPUT ;
    USE SIGNAL ;
    PORT
      LAYER M4 ;
        RECT  0 32.496 0.084 32.52 ;
    END
  END r_q[271]
  PIN r_q[272]
    DIRECTION OUTPUT ;
    USE SIGNAL ;
    PORT
      LAYER M4 ;
        RECT  0 32.592 0.084 32.616 ;
    END
  END r_q[272]
  PIN r_q[273]
    DIRECTION OUTPUT ;
    USE SIGNAL ;
    PORT
      LAYER M4 ;
        RECT  0 10.416 0.084 10.44 ;
    END
  END r_q[273]
  PIN r_q[274]
    DIRECTION OUTPUT ;
    USE SIGNAL ;
    PORT
      LAYER M4 ;
        RECT  0 10.512 0.084 10.536 ;
    END
  END r_q[274]
  PIN r_q[275]
    DIRECTION OUTPUT ;
    USE SIGNAL ;
    PORT
      LAYER M4 ;
        RECT  0 10.608 0.084 10.632 ;
    END
  END r_q[275]
  PIN r_q[276]
    DIRECTION OUTPUT ;
    USE SIGNAL ;
    PORT
      LAYER M4 ;
        RECT  0 10.704 0.084 10.728 ;
    END
  END r_q[276]
  PIN r_q[277]
    DIRECTION OUTPUT ;
    USE SIGNAL ;
    PORT
      LAYER M4 ;
        RECT  0 10.8 0.084 10.824 ;
    END
  END r_q[277]
  PIN r_q[278]
    DIRECTION OUTPUT ;
    USE SIGNAL ;
    PORT
      LAYER M4 ;
        RECT  0 10.896 0.084 10.92 ;
    END
  END r_q[278]
  PIN r_q[279]
    DIRECTION OUTPUT ;
    USE SIGNAL ;
    PORT
      LAYER M4 ;
        RECT  0 10.992 0.084 11.016 ;
    END
  END r_q[279]
  PIN r_q[27]
    DIRECTION OUTPUT ;
    USE SIGNAL ;
    PORT
      LAYER M4 ;
        RECT  0 5.232 0.084 5.256 ;
    END
  END r_q[27]
  PIN r_q[280]
    DIRECTION OUTPUT ;
    USE SIGNAL ;
    PORT
      LAYER M4 ;
        RECT  0 11.088 0.084 11.112 ;
    END
  END r_q[280]
  PIN r_q[281]
    DIRECTION OUTPUT ;
    USE SIGNAL ;
    PORT
      LAYER M4 ;
        RECT  0 11.184 0.084 11.208 ;
    END
  END r_q[281]
  PIN r_q[282]
    DIRECTION OUTPUT ;
    USE SIGNAL ;
    PORT
      LAYER M4 ;
        RECT  0 11.28 0.084 11.304 ;
    END
  END r_q[282]
  PIN r_q[283]
    DIRECTION OUTPUT ;
    USE SIGNAL ;
    PORT
      LAYER M4 ;
        RECT  0 11.376 0.084 11.4 ;
    END
  END r_q[283]
  PIN r_q[284]
    DIRECTION OUTPUT ;
    USE SIGNAL ;
    PORT
      LAYER M4 ;
        RECT  0 11.472 0.084 11.496 ;
    END
  END r_q[284]
  PIN r_q[285]
    DIRECTION OUTPUT ;
    USE SIGNAL ;
    PORT
      LAYER M4 ;
        RECT  0 11.568 0.084 11.592 ;
    END
  END r_q[285]
  PIN r_q[286]
    DIRECTION OUTPUT ;
    USE SIGNAL ;
    PORT
      LAYER M4 ;
        RECT  0 11.664 0.084 11.688 ;
    END
  END r_q[286]
  PIN r_q[287]
    DIRECTION OUTPUT ;
    USE SIGNAL ;
    PORT
      LAYER M4 ;
        RECT  0 11.76 0.084 11.784 ;
    END
  END r_q[287]
  PIN r_q[288]
    DIRECTION OUTPUT ;
    USE SIGNAL ;
    PORT
      LAYER M4 ;
        RECT  0 11.856 0.084 11.88 ;
    END
  END r_q[288]
  PIN r_q[289]
    DIRECTION OUTPUT ;
    USE SIGNAL ;
    PORT
      LAYER M4 ;
        RECT  0 11.952 0.084 11.976 ;
    END
  END r_q[289]
  PIN r_q[28]
    DIRECTION OUTPUT ;
    USE SIGNAL ;
    PORT
      LAYER M4 ;
        RECT  0 5.328 0.084 5.352 ;
    END
  END r_q[28]
  PIN r_q[290]
    DIRECTION OUTPUT ;
    USE SIGNAL ;
    PORT
      LAYER M4 ;
        RECT  0 12.048 0.084 12.072 ;
    END
  END r_q[290]
  PIN r_q[291]
    DIRECTION OUTPUT ;
    USE SIGNAL ;
    PORT
      LAYER M4 ;
        RECT  0 12.144 0.084 12.168 ;
    END
  END r_q[291]
  PIN r_q[292]
    DIRECTION OUTPUT ;
    USE SIGNAL ;
    PORT
      LAYER M4 ;
        RECT  0 12.24 0.084 12.264 ;
    END
  END r_q[292]
  PIN r_q[293]
    DIRECTION OUTPUT ;
    USE SIGNAL ;
    PORT
      LAYER M4 ;
        RECT  0 12.336 0.084 12.36 ;
    END
  END r_q[293]
  PIN r_q[294]
    DIRECTION OUTPUT ;
    USE SIGNAL ;
    PORT
      LAYER M4 ;
        RECT  0 12.432 0.084 12.456 ;
    END
  END r_q[294]
  PIN r_q[295]
    DIRECTION OUTPUT ;
    USE SIGNAL ;
    PORT
      LAYER M4 ;
        RECT  0 12.528 0.084 12.552 ;
    END
  END r_q[295]
  PIN r_q[296]
    DIRECTION OUTPUT ;
    USE SIGNAL ;
    PORT
      LAYER M4 ;
        RECT  0 12.624 0.084 12.648 ;
    END
  END r_q[296]
  PIN r_q[297]
    DIRECTION OUTPUT ;
    USE SIGNAL ;
    PORT
      LAYER M4 ;
        RECT  0 12.72 0.084 12.744 ;
    END
  END r_q[297]
  PIN r_q[298]
    DIRECTION OUTPUT ;
    USE SIGNAL ;
    PORT
      LAYER M4 ;
        RECT  0 12.816 0.084 12.84 ;
    END
  END r_q[298]
  PIN r_q[299]
    DIRECTION OUTPUT ;
    USE SIGNAL ;
    PORT
      LAYER M4 ;
        RECT  0 12.912 0.084 12.936 ;
    END
  END r_q[299]
  PIN r_q[29]
    DIRECTION OUTPUT ;
    USE SIGNAL ;
    PORT
      LAYER M4 ;
        RECT  0 5.424 0.084 5.448 ;
    END
  END r_q[29]
  PIN r_q[2]
    DIRECTION OUTPUT ;
    USE SIGNAL ;
    PORT
      LAYER M4 ;
        RECT  0 22.032 0.084 22.056 ;
    END
  END r_q[2]
  PIN r_q[300]
    DIRECTION OUTPUT ;
    USE SIGNAL ;
    PORT
      LAYER M4 ;
        RECT  0 13.008 0.084 13.032 ;
    END
  END r_q[300]
  PIN r_q[301]
    DIRECTION OUTPUT ;
    USE SIGNAL ;
    PORT
      LAYER M4 ;
        RECT  0 13.104 0.084 13.128 ;
    END
  END r_q[301]
  PIN r_q[302]
    DIRECTION OUTPUT ;
    USE SIGNAL ;
    PORT
      LAYER M4 ;
        RECT  0 13.2 0.084 13.224 ;
    END
  END r_q[302]
  PIN r_q[303]
    DIRECTION OUTPUT ;
    USE SIGNAL ;
    PORT
      LAYER M4 ;
        RECT  0 13.296 0.084 13.32 ;
    END
  END r_q[303]
  PIN r_q[304]
    DIRECTION OUTPUT ;
    USE SIGNAL ;
    PORT
      LAYER M4 ;
        RECT  0 13.392 0.084 13.416 ;
    END
  END r_q[304]
  PIN r_q[305]
    DIRECTION OUTPUT ;
    USE SIGNAL ;
    PORT
      LAYER M4 ;
        RECT  0 7.344 0.084 7.368 ;
    END
  END r_q[305]
  PIN r_q[306]
    DIRECTION OUTPUT ;
    USE SIGNAL ;
    PORT
      LAYER M4 ;
        RECT  0 7.44 0.084 7.464 ;
    END
  END r_q[306]
  PIN r_q[307]
    DIRECTION OUTPUT ;
    USE SIGNAL ;
    PORT
      LAYER M4 ;
        RECT  0 7.536 0.084 7.56 ;
    END
  END r_q[307]
  PIN r_q[308]
    DIRECTION OUTPUT ;
    USE SIGNAL ;
    PORT
      LAYER M4 ;
        RECT  0 7.632 0.084 7.656 ;
    END
  END r_q[308]
  PIN r_q[309]
    DIRECTION OUTPUT ;
    USE SIGNAL ;
    PORT
      LAYER M4 ;
        RECT  0 7.728 0.084 7.752 ;
    END
  END r_q[309]
  PIN r_q[30]
    DIRECTION OUTPUT ;
    USE SIGNAL ;
    PORT
      LAYER M4 ;
        RECT  0 5.52 0.084 5.544 ;
    END
  END r_q[30]
  PIN r_q[310]
    DIRECTION OUTPUT ;
    USE SIGNAL ;
    PORT
      LAYER M4 ;
        RECT  0 7.824 0.084 7.848 ;
    END
  END r_q[310]
  PIN r_q[311]
    DIRECTION OUTPUT ;
    USE SIGNAL ;
    PORT
      LAYER M4 ;
        RECT  0 7.92 0.084 7.944 ;
    END
  END r_q[311]
  PIN r_q[312]
    DIRECTION OUTPUT ;
    USE SIGNAL ;
    PORT
      LAYER M4 ;
        RECT  0 8.016 0.084 8.04 ;
    END
  END r_q[312]
  PIN r_q[313]
    DIRECTION OUTPUT ;
    USE SIGNAL ;
    PORT
      LAYER M4 ;
        RECT  0 8.112 0.084 8.136 ;
    END
  END r_q[313]
  PIN r_q[314]
    DIRECTION OUTPUT ;
    USE SIGNAL ;
    PORT
      LAYER M4 ;
        RECT  0 8.208 0.084 8.232 ;
    END
  END r_q[314]
  PIN r_q[315]
    DIRECTION OUTPUT ;
    USE SIGNAL ;
    PORT
      LAYER M4 ;
        RECT  0 8.304 0.084 8.328 ;
    END
  END r_q[315]
  PIN r_q[316]
    DIRECTION OUTPUT ;
    USE SIGNAL ;
    PORT
      LAYER M4 ;
        RECT  0 8.4 0.084 8.424 ;
    END
  END r_q[316]
  PIN r_q[317]
    DIRECTION OUTPUT ;
    USE SIGNAL ;
    PORT
      LAYER M4 ;
        RECT  0 8.496 0.084 8.52 ;
    END
  END r_q[317]
  PIN r_q[318]
    DIRECTION OUTPUT ;
    USE SIGNAL ;
    PORT
      LAYER M4 ;
        RECT  0 8.592 0.084 8.616 ;
    END
  END r_q[318]
  PIN r_q[319]
    DIRECTION OUTPUT ;
    USE SIGNAL ;
    PORT
      LAYER M4 ;
        RECT  0 8.688 0.084 8.712 ;
    END
  END r_q[319]
  PIN r_q[31]
    DIRECTION OUTPUT ;
    USE SIGNAL ;
    PORT
      LAYER M4 ;
        RECT  0 5.616 0.084 5.64 ;
    END
  END r_q[31]
  PIN r_q[320]
    DIRECTION OUTPUT ;
    USE SIGNAL ;
    PORT
      LAYER M4 ;
        RECT  0 8.784 0.084 8.808 ;
    END
  END r_q[320]
  PIN r_q[321]
    DIRECTION OUTPUT ;
    USE SIGNAL ;
    PORT
      LAYER M4 ;
        RECT  0 8.88 0.084 8.904 ;
    END
  END r_q[321]
  PIN r_q[322]
    DIRECTION OUTPUT ;
    USE SIGNAL ;
    PORT
      LAYER M4 ;
        RECT  0 8.976 0.084 9 ;
    END
  END r_q[322]
  PIN r_q[323]
    DIRECTION OUTPUT ;
    USE SIGNAL ;
    PORT
      LAYER M4 ;
        RECT  0 9.072 0.084 9.096 ;
    END
  END r_q[323]
  PIN r_q[324]
    DIRECTION OUTPUT ;
    USE SIGNAL ;
    PORT
      LAYER M4 ;
        RECT  0 9.168 0.084 9.192 ;
    END
  END r_q[324]
  PIN r_q[325]
    DIRECTION OUTPUT ;
    USE SIGNAL ;
    PORT
      LAYER M4 ;
        RECT  0 9.264 0.084 9.288 ;
    END
  END r_q[325]
  PIN r_q[326]
    DIRECTION OUTPUT ;
    USE SIGNAL ;
    PORT
      LAYER M4 ;
        RECT  0 9.36 0.084 9.384 ;
    END
  END r_q[326]
  PIN r_q[327]
    DIRECTION OUTPUT ;
    USE SIGNAL ;
    PORT
      LAYER M4 ;
        RECT  0 9.456 0.084 9.48 ;
    END
  END r_q[327]
  PIN r_q[328]
    DIRECTION OUTPUT ;
    USE SIGNAL ;
    PORT
      LAYER M4 ;
        RECT  0 9.552 0.084 9.576 ;
    END
  END r_q[328]
  PIN r_q[329]
    DIRECTION OUTPUT ;
    USE SIGNAL ;
    PORT
      LAYER M4 ;
        RECT  0 9.648 0.084 9.672 ;
    END
  END r_q[329]
  PIN r_q[32]
    DIRECTION OUTPUT ;
    USE SIGNAL ;
    PORT
      LAYER M4 ;
        RECT  0 5.712 0.084 5.736 ;
    END
  END r_q[32]
  PIN r_q[330]
    DIRECTION OUTPUT ;
    USE SIGNAL ;
    PORT
      LAYER M4 ;
        RECT  0 9.744 0.084 9.768 ;
    END
  END r_q[330]
  PIN r_q[331]
    DIRECTION OUTPUT ;
    USE SIGNAL ;
    PORT
      LAYER M4 ;
        RECT  0 9.84 0.084 9.864 ;
    END
  END r_q[331]
  PIN r_q[332]
    DIRECTION OUTPUT ;
    USE SIGNAL ;
    PORT
      LAYER M4 ;
        RECT  0 9.936 0.084 9.96 ;
    END
  END r_q[332]
  PIN r_q[333]
    DIRECTION OUTPUT ;
    USE SIGNAL ;
    PORT
      LAYER M4 ;
        RECT  0 10.032 0.084 10.056 ;
    END
  END r_q[333]
  PIN r_q[334]
    DIRECTION OUTPUT ;
    USE SIGNAL ;
    PORT
      LAYER M4 ;
        RECT  0 10.128 0.084 10.152 ;
    END
  END r_q[334]
  PIN r_q[335]
    DIRECTION OUTPUT ;
    USE SIGNAL ;
    PORT
      LAYER M4 ;
        RECT  0 10.224 0.084 10.248 ;
    END
  END r_q[335]
  PIN r_q[336]
    DIRECTION OUTPUT ;
    USE SIGNAL ;
    PORT
      LAYER M4 ;
        RECT  0 10.32 0.084 10.344 ;
    END
  END r_q[336]
  PIN r_q[337]
    DIRECTION OUTPUT ;
    USE SIGNAL ;
    PORT
      LAYER M4 ;
        RECT  0 1.2 0.084 1.224 ;
    END
  END r_q[337]
  PIN r_q[338]
    DIRECTION OUTPUT ;
    USE SIGNAL ;
    PORT
      LAYER M4 ;
        RECT  0 1.296 0.084 1.32 ;
    END
  END r_q[338]
  PIN r_q[339]
    DIRECTION OUTPUT ;
    USE SIGNAL ;
    PORT
      LAYER M4 ;
        RECT  0 1.392 0.084 1.416 ;
    END
  END r_q[339]
  PIN r_q[33]
    DIRECTION OUTPUT ;
    USE SIGNAL ;
    PORT
      LAYER M4 ;
        RECT  0 5.808 0.084 5.832 ;
    END
  END r_q[33]
  PIN r_q[340]
    DIRECTION OUTPUT ;
    USE SIGNAL ;
    PORT
      LAYER M4 ;
        RECT  0 1.488 0.084 1.512 ;
    END
  END r_q[340]
  PIN r_q[341]
    DIRECTION OUTPUT ;
    USE SIGNAL ;
    PORT
      LAYER M4 ;
        RECT  0 1.584 0.084 1.608 ;
    END
  END r_q[341]
  PIN r_q[342]
    DIRECTION OUTPUT ;
    USE SIGNAL ;
    PORT
      LAYER M4 ;
        RECT  0 1.68 0.084 1.704 ;
    END
  END r_q[342]
  PIN r_q[343]
    DIRECTION OUTPUT ;
    USE SIGNAL ;
    PORT
      LAYER M4 ;
        RECT  0 1.776 0.084 1.8 ;
    END
  END r_q[343]
  PIN r_q[344]
    DIRECTION OUTPUT ;
    USE SIGNAL ;
    PORT
      LAYER M4 ;
        RECT  0 1.872 0.084 1.896 ;
    END
  END r_q[344]
  PIN r_q[345]
    DIRECTION OUTPUT ;
    USE SIGNAL ;
    PORT
      LAYER M4 ;
        RECT  0 1.968 0.084 1.992 ;
    END
  END r_q[345]
  PIN r_q[346]
    DIRECTION OUTPUT ;
    USE SIGNAL ;
    PORT
      LAYER M4 ;
        RECT  0 2.064 0.084 2.088 ;
    END
  END r_q[346]
  PIN r_q[347]
    DIRECTION OUTPUT ;
    USE SIGNAL ;
    PORT
      LAYER M4 ;
        RECT  0 2.16 0.084 2.184 ;
    END
  END r_q[347]
  PIN r_q[348]
    DIRECTION OUTPUT ;
    USE SIGNAL ;
    PORT
      LAYER M4 ;
        RECT  0 2.256 0.084 2.28 ;
    END
  END r_q[348]
  PIN r_q[349]
    DIRECTION OUTPUT ;
    USE SIGNAL ;
    PORT
      LAYER M4 ;
        RECT  0 2.352 0.084 2.376 ;
    END
  END r_q[349]
  PIN r_q[34]
    DIRECTION OUTPUT ;
    USE SIGNAL ;
    PORT
      LAYER M4 ;
        RECT  0 5.904 0.084 5.928 ;
    END
  END r_q[34]
  PIN r_q[350]
    DIRECTION OUTPUT ;
    USE SIGNAL ;
    PORT
      LAYER M4 ;
        RECT  0 2.448 0.084 2.472 ;
    END
  END r_q[350]
  PIN r_q[351]
    DIRECTION OUTPUT ;
    USE SIGNAL ;
    PORT
      LAYER M4 ;
        RECT  0 2.544 0.084 2.568 ;
    END
  END r_q[351]
  PIN r_q[352]
    DIRECTION OUTPUT ;
    USE SIGNAL ;
    PORT
      LAYER M4 ;
        RECT  0 2.64 0.084 2.664 ;
    END
  END r_q[352]
  PIN r_q[353]
    DIRECTION OUTPUT ;
    USE SIGNAL ;
    PORT
      LAYER M4 ;
        RECT  0 2.736 0.084 2.76 ;
    END
  END r_q[353]
  PIN r_q[354]
    DIRECTION OUTPUT ;
    USE SIGNAL ;
    PORT
      LAYER M4 ;
        RECT  0 2.832 0.084 2.856 ;
    END
  END r_q[354]
  PIN r_q[355]
    DIRECTION OUTPUT ;
    USE SIGNAL ;
    PORT
      LAYER M4 ;
        RECT  0 2.928 0.084 2.952 ;
    END
  END r_q[355]
  PIN r_q[356]
    DIRECTION OUTPUT ;
    USE SIGNAL ;
    PORT
      LAYER M4 ;
        RECT  0 3.024 0.084 3.048 ;
    END
  END r_q[356]
  PIN r_q[357]
    DIRECTION OUTPUT ;
    USE SIGNAL ;
    PORT
      LAYER M4 ;
        RECT  0 3.12 0.084 3.144 ;
    END
  END r_q[357]
  PIN r_q[358]
    DIRECTION OUTPUT ;
    USE SIGNAL ;
    PORT
      LAYER M4 ;
        RECT  0 3.216 0.084 3.24 ;
    END
  END r_q[358]
  PIN r_q[359]
    DIRECTION OUTPUT ;
    USE SIGNAL ;
    PORT
      LAYER M4 ;
        RECT  0 3.312 0.084 3.336 ;
    END
  END r_q[359]
  PIN r_q[35]
    DIRECTION OUTPUT ;
    USE SIGNAL ;
    PORT
      LAYER M4 ;
        RECT  0 6 0.084 6.024 ;
    END
  END r_q[35]
  PIN r_q[360]
    DIRECTION OUTPUT ;
    USE SIGNAL ;
    PORT
      LAYER M4 ;
        RECT  0 3.408 0.084 3.432 ;
    END
  END r_q[360]
  PIN r_q[361]
    DIRECTION OUTPUT ;
    USE SIGNAL ;
    PORT
      LAYER M4 ;
        RECT  0 3.504 0.084 3.528 ;
    END
  END r_q[361]
  PIN r_q[362]
    DIRECTION OUTPUT ;
    USE SIGNAL ;
    PORT
      LAYER M4 ;
        RECT  0 3.6 0.084 3.624 ;
    END
  END r_q[362]
  PIN r_q[363]
    DIRECTION OUTPUT ;
    USE SIGNAL ;
    PORT
      LAYER M4 ;
        RECT  0 3.696 0.084 3.72 ;
    END
  END r_q[363]
  PIN r_q[364]
    DIRECTION OUTPUT ;
    USE SIGNAL ;
    PORT
      LAYER M4 ;
        RECT  0 3.792 0.084 3.816 ;
    END
  END r_q[364]
  PIN r_q[365]
    DIRECTION OUTPUT ;
    USE SIGNAL ;
    PORT
      LAYER M4 ;
        RECT  0 3.888 0.084 3.912 ;
    END
  END r_q[365]
  PIN r_q[366]
    DIRECTION OUTPUT ;
    USE SIGNAL ;
    PORT
      LAYER M4 ;
        RECT  0 3.984 0.084 4.008 ;
    END
  END r_q[366]
  PIN r_q[367]
    DIRECTION OUTPUT ;
    USE SIGNAL ;
    PORT
      LAYER M4 ;
        RECT  0 4.08 0.084 4.104 ;
    END
  END r_q[367]
  PIN r_q[368]
    DIRECTION OUTPUT ;
    USE SIGNAL ;
    PORT
      LAYER M4 ;
        RECT  0 4.176 0.084 4.2 ;
    END
  END r_q[368]
  PIN r_q[369]
    DIRECTION OUTPUT ;
    USE SIGNAL ;
    PORT
      LAYER M4 ;
        RECT  0 33.456 0.084 33.48 ;
    END
  END r_q[369]
  PIN r_q[36]
    DIRECTION OUTPUT ;
    USE SIGNAL ;
    PORT
      LAYER M4 ;
        RECT  0 6.096 0.084 6.12 ;
    END
  END r_q[36]
  PIN r_q[370]
    DIRECTION OUTPUT ;
    USE SIGNAL ;
    PORT
      LAYER M4 ;
        RECT  0 33.552 0.084 33.576 ;
    END
  END r_q[370]
  PIN r_q[371]
    DIRECTION OUTPUT ;
    USE SIGNAL ;
    PORT
      LAYER M4 ;
        RECT  0 33.648 0.084 33.672 ;
    END
  END r_q[371]
  PIN r_q[372]
    DIRECTION OUTPUT ;
    USE SIGNAL ;
    PORT
      LAYER M4 ;
        RECT  0 33.744 0.084 33.768 ;
    END
  END r_q[372]
  PIN r_q[373]
    DIRECTION OUTPUT ;
    USE SIGNAL ;
    PORT
      LAYER M4 ;
        RECT  0 33.84 0.084 33.864 ;
    END
  END r_q[373]
  PIN r_q[374]
    DIRECTION OUTPUT ;
    USE SIGNAL ;
    PORT
      LAYER M4 ;
        RECT  0 33.936 0.084 33.96 ;
    END
  END r_q[374]
  PIN r_q[375]
    DIRECTION OUTPUT ;
    USE SIGNAL ;
    PORT
      LAYER M4 ;
        RECT  0 34.032 0.084 34.056 ;
    END
  END r_q[375]
  PIN r_q[376]
    DIRECTION OUTPUT ;
    USE SIGNAL ;
    PORT
      LAYER M4 ;
        RECT  0 34.128 0.084 34.152 ;
    END
  END r_q[376]
  PIN r_q[377]
    DIRECTION OUTPUT ;
    USE SIGNAL ;
    PORT
      LAYER M4 ;
        RECT  0 34.224 0.084 34.248 ;
    END
  END r_q[377]
  PIN r_q[378]
    DIRECTION OUTPUT ;
    USE SIGNAL ;
    PORT
      LAYER M4 ;
        RECT  0 34.32 0.084 34.344 ;
    END
  END r_q[378]
  PIN r_q[379]
    DIRECTION OUTPUT ;
    USE SIGNAL ;
    PORT
      LAYER M4 ;
        RECT  0 34.416 0.084 34.44 ;
    END
  END r_q[379]
  PIN r_q[37]
    DIRECTION OUTPUT ;
    USE SIGNAL ;
    PORT
      LAYER M4 ;
        RECT  0 6.192 0.084 6.216 ;
    END
  END r_q[37]
  PIN r_q[380]
    DIRECTION OUTPUT ;
    USE SIGNAL ;
    PORT
      LAYER M4 ;
        RECT  0 34.512 0.084 34.536 ;
    END
  END r_q[380]
  PIN r_q[381]
    DIRECTION OUTPUT ;
    USE SIGNAL ;
    PORT
      LAYER M4 ;
        RECT  0 34.608 0.084 34.632 ;
    END
  END r_q[381]
  PIN r_q[382]
    DIRECTION OUTPUT ;
    USE SIGNAL ;
    PORT
      LAYER M4 ;
        RECT  0 34.704 0.084 34.728 ;
    END
  END r_q[382]
  PIN r_q[383]
    DIRECTION OUTPUT ;
    USE SIGNAL ;
    PORT
      LAYER M4 ;
        RECT  0 34.8 0.084 34.824 ;
    END
  END r_q[383]
  PIN r_q[384]
    DIRECTION OUTPUT ;
    USE SIGNAL ;
    PORT
      LAYER M4 ;
        RECT  0 34.896 0.084 34.92 ;
    END
  END r_q[384]
  PIN r_q[385]
    DIRECTION OUTPUT ;
    USE SIGNAL ;
    PORT
      LAYER M4 ;
        RECT  0 34.992 0.084 35.016 ;
    END
  END r_q[385]
  PIN r_q[386]
    DIRECTION OUTPUT ;
    USE SIGNAL ;
    PORT
      LAYER M4 ;
        RECT  0 35.088 0.084 35.112 ;
    END
  END r_q[386]
  PIN r_q[387]
    DIRECTION OUTPUT ;
    USE SIGNAL ;
    PORT
      LAYER M4 ;
        RECT  0 35.184 0.084 35.208 ;
    END
  END r_q[387]
  PIN r_q[388]
    DIRECTION OUTPUT ;
    USE SIGNAL ;
    PORT
      LAYER M4 ;
        RECT  0 35.28 0.084 35.304 ;
    END
  END r_q[388]
  PIN r_q[389]
    DIRECTION OUTPUT ;
    USE SIGNAL ;
    PORT
      LAYER M4 ;
        RECT  0 35.376 0.084 35.4 ;
    END
  END r_q[389]
  PIN r_q[38]
    DIRECTION OUTPUT ;
    USE SIGNAL ;
    PORT
      LAYER M4 ;
        RECT  0 6.288 0.084 6.312 ;
    END
  END r_q[38]
  PIN r_q[390]
    DIRECTION OUTPUT ;
    USE SIGNAL ;
    PORT
      LAYER M4 ;
        RECT  0 35.472 0.084 35.496 ;
    END
  END r_q[390]
  PIN r_q[391]
    DIRECTION OUTPUT ;
    USE SIGNAL ;
    PORT
      LAYER M4 ;
        RECT  0 35.568 0.084 35.592 ;
    END
  END r_q[391]
  PIN r_q[392]
    DIRECTION OUTPUT ;
    USE SIGNAL ;
    PORT
      LAYER M4 ;
        RECT  0 35.664 0.084 35.688 ;
    END
  END r_q[392]
  PIN r_q[393]
    DIRECTION OUTPUT ;
    USE SIGNAL ;
    PORT
      LAYER M4 ;
        RECT  0 35.76 0.084 35.784 ;
    END
  END r_q[393]
  PIN r_q[394]
    DIRECTION OUTPUT ;
    USE SIGNAL ;
    PORT
      LAYER M4 ;
        RECT  0 35.856 0.084 35.88 ;
    END
  END r_q[394]
  PIN r_q[395]
    DIRECTION OUTPUT ;
    USE SIGNAL ;
    PORT
      LAYER M4 ;
        RECT  0 35.952 0.084 35.976 ;
    END
  END r_q[395]
  PIN r_q[396]
    DIRECTION OUTPUT ;
    USE SIGNAL ;
    PORT
      LAYER M4 ;
        RECT  0 36.048 0.084 36.072 ;
    END
  END r_q[396]
  PIN r_q[397]
    DIRECTION OUTPUT ;
    USE SIGNAL ;
    PORT
      LAYER M4 ;
        RECT  0 36.144 0.084 36.168 ;
    END
  END r_q[397]
  PIN r_q[398]
    DIRECTION OUTPUT ;
    USE SIGNAL ;
    PORT
      LAYER M4 ;
        RECT  0 36.24 0.084 36.264 ;
    END
  END r_q[398]
  PIN r_q[399]
    DIRECTION OUTPUT ;
    USE SIGNAL ;
    PORT
      LAYER M4 ;
        RECT  0 36.336 0.084 36.36 ;
    END
  END r_q[399]
  PIN r_q[39]
    DIRECTION OUTPUT ;
    USE SIGNAL ;
    PORT
      LAYER M4 ;
        RECT  0 6.384 0.084 6.408 ;
    END
  END r_q[39]
  PIN r_q[3]
    DIRECTION OUTPUT ;
    USE SIGNAL ;
    PORT
      LAYER M4 ;
        RECT  0 22.128 0.084 22.152 ;
    END
  END r_q[3]
  PIN r_q[400]
    DIRECTION OUTPUT ;
    USE SIGNAL ;
    PORT
      LAYER M4 ;
        RECT  0 36.432 0.084 36.456 ;
    END
  END r_q[400]
  PIN r_q[401]
    DIRECTION OUTPUT ;
    USE SIGNAL ;
    PORT
      LAYER M4 ;
        RECT  0 36.528 0.084 36.552 ;
    END
  END r_q[401]
  PIN r_q[402]
    DIRECTION OUTPUT ;
    USE SIGNAL ;
    PORT
      LAYER M4 ;
        RECT  0 36.624 0.084 36.648 ;
    END
  END r_q[402]
  PIN r_q[403]
    DIRECTION OUTPUT ;
    USE SIGNAL ;
    PORT
      LAYER M4 ;
        RECT  0 36.72 0.084 36.744 ;
    END
  END r_q[403]
  PIN r_q[404]
    DIRECTION OUTPUT ;
    USE SIGNAL ;
    PORT
      LAYER M4 ;
        RECT  0 36.816 0.084 36.84 ;
    END
  END r_q[404]
  PIN r_q[405]
    DIRECTION OUTPUT ;
    USE SIGNAL ;
    PORT
      LAYER M4 ;
        RECT  0 36.912 0.084 36.936 ;
    END
  END r_q[405]
  PIN r_q[406]
    DIRECTION OUTPUT ;
    USE SIGNAL ;
    PORT
      LAYER M4 ;
        RECT  0 37.008 0.084 37.032 ;
    END
  END r_q[406]
  PIN r_q[407]
    DIRECTION OUTPUT ;
    USE SIGNAL ;
    PORT
      LAYER M4 ;
        RECT  0 37.104 0.084 37.128 ;
    END
  END r_q[407]
  PIN r_q[408]
    DIRECTION OUTPUT ;
    USE SIGNAL ;
    PORT
      LAYER M4 ;
        RECT  0 37.2 0.084 37.224 ;
    END
  END r_q[408]
  PIN r_q[409]
    DIRECTION OUTPUT ;
    USE SIGNAL ;
    PORT
      LAYER M4 ;
        RECT  0 37.296 0.084 37.32 ;
    END
  END r_q[409]
  PIN r_q[40]
    DIRECTION OUTPUT ;
    USE SIGNAL ;
    PORT
      LAYER M4 ;
        RECT  0 6.48 0.084 6.504 ;
    END
  END r_q[40]
  PIN r_q[410]
    DIRECTION OUTPUT ;
    USE SIGNAL ;
    PORT
      LAYER M4 ;
        RECT  0 37.392 0.084 37.416 ;
    END
  END r_q[410]
  PIN r_q[411]
    DIRECTION OUTPUT ;
    USE SIGNAL ;
    PORT
      LAYER M4 ;
        RECT  0 37.488 0.084 37.512 ;
    END
  END r_q[411]
  PIN r_q[412]
    DIRECTION OUTPUT ;
    USE SIGNAL ;
    PORT
      LAYER M4 ;
        RECT  0 37.584 0.084 37.608 ;
    END
  END r_q[412]
  PIN r_q[413]
    DIRECTION OUTPUT ;
    USE SIGNAL ;
    PORT
      LAYER M4 ;
        RECT  0 37.68 0.084 37.704 ;
    END
  END r_q[413]
  PIN r_q[414]
    DIRECTION OUTPUT ;
    USE SIGNAL ;
    PORT
      LAYER M4 ;
        RECT  0 37.776 0.084 37.8 ;
    END
  END r_q[414]
  PIN r_q[415]
    DIRECTION OUTPUT ;
    USE SIGNAL ;
    PORT
      LAYER M4 ;
        RECT  0 37.872 0.084 37.896 ;
    END
  END r_q[415]
  PIN r_q[416]
    DIRECTION OUTPUT ;
    USE SIGNAL ;
    PORT
      LAYER M4 ;
        RECT  0 37.968 0.084 37.992 ;
    END
  END r_q[416]
  PIN r_q[417]
    DIRECTION OUTPUT ;
    USE SIGNAL ;
    PORT
      LAYER M4 ;
        RECT  0 38.064 0.084 38.088 ;
    END
  END r_q[417]
  PIN r_q[418]
    DIRECTION OUTPUT ;
    USE SIGNAL ;
    PORT
      LAYER M4 ;
        RECT  0 38.16 0.084 38.184 ;
    END
  END r_q[418]
  PIN r_q[419]
    DIRECTION OUTPUT ;
    USE SIGNAL ;
    PORT
      LAYER M4 ;
        RECT  0 38.256 0.084 38.28 ;
    END
  END r_q[419]
  PIN r_q[41]
    DIRECTION OUTPUT ;
    USE SIGNAL ;
    PORT
      LAYER M4 ;
        RECT  0 6.576 0.084 6.6 ;
    END
  END r_q[41]
  PIN r_q[420]
    DIRECTION OUTPUT ;
    USE SIGNAL ;
    PORT
      LAYER M4 ;
        RECT  0 38.352 0.084 38.376 ;
    END
  END r_q[420]
  PIN r_q[421]
    DIRECTION OUTPUT ;
    USE SIGNAL ;
    PORT
      LAYER M4 ;
        RECT  0 38.448 0.084 38.472 ;
    END
  END r_q[421]
  PIN r_q[422]
    DIRECTION OUTPUT ;
    USE SIGNAL ;
    PORT
      LAYER M4 ;
        RECT  0 38.544 0.084 38.568 ;
    END
  END r_q[422]
  PIN r_q[423]
    DIRECTION OUTPUT ;
    USE SIGNAL ;
    PORT
      LAYER M4 ;
        RECT  0 38.64 0.084 38.664 ;
    END
  END r_q[423]
  PIN r_q[424]
    DIRECTION OUTPUT ;
    USE SIGNAL ;
    PORT
      LAYER M4 ;
        RECT  0 38.736 0.084 38.76 ;
    END
  END r_q[424]
  PIN r_q[425]
    DIRECTION OUTPUT ;
    USE SIGNAL ;
    PORT
      LAYER M4 ;
        RECT  0 38.832 0.084 38.856 ;
    END
  END r_q[425]
  PIN r_q[426]
    DIRECTION OUTPUT ;
    USE SIGNAL ;
    PORT
      LAYER M4 ;
        RECT  0 38.928 0.084 38.952 ;
    END
  END r_q[426]
  PIN r_q[427]
    DIRECTION OUTPUT ;
    USE SIGNAL ;
    PORT
      LAYER M4 ;
        RECT  0 39.024 0.084 39.048 ;
    END
  END r_q[427]
  PIN r_q[428]
    DIRECTION OUTPUT ;
    USE SIGNAL ;
    PORT
      LAYER M4 ;
        RECT  0 39.12 0.084 39.144 ;
    END
  END r_q[428]
  PIN r_q[429]
    DIRECTION OUTPUT ;
    USE SIGNAL ;
    PORT
      LAYER M4 ;
        RECT  0 39.216 0.084 39.24 ;
    END
  END r_q[429]
  PIN r_q[42]
    DIRECTION OUTPUT ;
    USE SIGNAL ;
    PORT
      LAYER M4 ;
        RECT  0 6.672 0.084 6.696 ;
    END
  END r_q[42]
  PIN r_q[430]
    DIRECTION OUTPUT ;
    USE SIGNAL ;
    PORT
      LAYER M4 ;
        RECT  0 39.312 0.084 39.336 ;
    END
  END r_q[430]
  PIN r_q[431]
    DIRECTION OUTPUT ;
    USE SIGNAL ;
    PORT
      LAYER M4 ;
        RECT  0 39.408 0.084 39.432 ;
    END
  END r_q[431]
  PIN r_q[432]
    DIRECTION OUTPUT ;
    USE SIGNAL ;
    PORT
      LAYER M4 ;
        RECT  0 39.504 0.084 39.528 ;
    END
  END r_q[432]
  PIN r_q[433]
    DIRECTION OUTPUT ;
    USE SIGNAL ;
    PORT
      LAYER M4 ;
        RECT  0 39.6 0.084 39.624 ;
    END
  END r_q[433]
  PIN r_q[434]
    DIRECTION OUTPUT ;
    USE SIGNAL ;
    PORT
      LAYER M4 ;
        RECT  0 39.696 0.084 39.72 ;
    END
  END r_q[434]
  PIN r_q[435]
    DIRECTION OUTPUT ;
    USE SIGNAL ;
    PORT
      LAYER M4 ;
        RECT  0 39.792 0.084 39.816 ;
    END
  END r_q[435]
  PIN r_q[436]
    DIRECTION OUTPUT ;
    USE SIGNAL ;
    PORT
      LAYER M4 ;
        RECT  0 39.888 0.084 39.912 ;
    END
  END r_q[436]
  PIN r_q[437]
    DIRECTION OUTPUT ;
    USE SIGNAL ;
    PORT
      LAYER M4 ;
        RECT  0 39.984 0.084 40.008 ;
    END
  END r_q[437]
  PIN r_q[438]
    DIRECTION OUTPUT ;
    USE SIGNAL ;
    PORT
      LAYER M4 ;
        RECT  0 40.08 0.084 40.104 ;
    END
  END r_q[438]
  PIN r_q[439]
    DIRECTION OUTPUT ;
    USE SIGNAL ;
    PORT
      LAYER M4 ;
        RECT  0 40.176 0.084 40.2 ;
    END
  END r_q[439]
  PIN r_q[43]
    DIRECTION OUTPUT ;
    USE SIGNAL ;
    PORT
      LAYER M4 ;
        RECT  0 6.768 0.084 6.792 ;
    END
  END r_q[43]
  PIN r_q[440]
    DIRECTION OUTPUT ;
    USE SIGNAL ;
    PORT
      LAYER M4 ;
        RECT  0 40.272 0.084 40.296 ;
    END
  END r_q[440]
  PIN r_q[441]
    DIRECTION OUTPUT ;
    USE SIGNAL ;
    PORT
      LAYER M4 ;
        RECT  0 40.368 0.084 40.392 ;
    END
  END r_q[441]
  PIN r_q[442]
    DIRECTION OUTPUT ;
    USE SIGNAL ;
    PORT
      LAYER M4 ;
        RECT  0 40.464 0.084 40.488 ;
    END
  END r_q[442]
  PIN r_q[443]
    DIRECTION OUTPUT ;
    USE SIGNAL ;
    PORT
      LAYER M4 ;
        RECT  0 40.56 0.084 40.584 ;
    END
  END r_q[443]
  PIN r_q[444]
    DIRECTION OUTPUT ;
    USE SIGNAL ;
    PORT
      LAYER M4 ;
        RECT  0 40.656 0.084 40.68 ;
    END
  END r_q[444]
  PIN r_q[445]
    DIRECTION OUTPUT ;
    USE SIGNAL ;
    PORT
      LAYER M4 ;
        RECT  0 40.752 0.084 40.776 ;
    END
  END r_q[445]
  PIN r_q[446]
    DIRECTION OUTPUT ;
    USE SIGNAL ;
    PORT
      LAYER M4 ;
        RECT  0 40.848 0.084 40.872 ;
    END
  END r_q[446]
  PIN r_q[447]
    DIRECTION OUTPUT ;
    USE SIGNAL ;
    PORT
      LAYER M4 ;
        RECT  0 40.944 0.084 40.968 ;
    END
  END r_q[447]
  PIN r_q[448]
    DIRECTION OUTPUT ;
    USE SIGNAL ;
    PORT
      LAYER M4 ;
        RECT  0 41.04 0.084 41.064 ;
    END
  END r_q[448]
  PIN r_q[449]
    DIRECTION OUTPUT ;
    USE SIGNAL ;
    PORT
      LAYER M4 ;
        RECT  0 41.136 0.084 41.16 ;
    END
  END r_q[449]
  PIN r_q[44]
    DIRECTION OUTPUT ;
    USE SIGNAL ;
    PORT
      LAYER M4 ;
        RECT  0 6.864 0.084 6.888 ;
    END
  END r_q[44]
  PIN r_q[450]
    DIRECTION OUTPUT ;
    USE SIGNAL ;
    PORT
      LAYER M4 ;
        RECT  0 41.232 0.084 41.256 ;
    END
  END r_q[450]
  PIN r_q[451]
    DIRECTION OUTPUT ;
    USE SIGNAL ;
    PORT
      LAYER M4 ;
        RECT  0 41.328 0.084 41.352 ;
    END
  END r_q[451]
  PIN r_q[452]
    DIRECTION OUTPUT ;
    USE SIGNAL ;
    PORT
      LAYER M4 ;
        RECT  0 41.424 0.084 41.448 ;
    END
  END r_q[452]
  PIN r_q[453]
    DIRECTION OUTPUT ;
    USE SIGNAL ;
    PORT
      LAYER M4 ;
        RECT  0 41.52 0.084 41.544 ;
    END
  END r_q[453]
  PIN r_q[454]
    DIRECTION OUTPUT ;
    USE SIGNAL ;
    PORT
      LAYER M4 ;
        RECT  0 41.616 0.084 41.64 ;
    END
  END r_q[454]
  PIN r_q[455]
    DIRECTION OUTPUT ;
    USE SIGNAL ;
    PORT
      LAYER M4 ;
        RECT  0 41.712 0.084 41.736 ;
    END
  END r_q[455]
  PIN r_q[456]
    DIRECTION OUTPUT ;
    USE SIGNAL ;
    PORT
      LAYER M4 ;
        RECT  0 41.808 0.084 41.832 ;
    END
  END r_q[456]
  PIN r_q[457]
    DIRECTION OUTPUT ;
    USE SIGNAL ;
    PORT
      LAYER M4 ;
        RECT  0 41.904 0.084 41.928 ;
    END
  END r_q[457]
  PIN r_q[458]
    DIRECTION OUTPUT ;
    USE SIGNAL ;
    PORT
      LAYER M4 ;
        RECT  0 42 0.084 42.024 ;
    END
  END r_q[458]
  PIN r_q[459]
    DIRECTION OUTPUT ;
    USE SIGNAL ;
    PORT
      LAYER M4 ;
        RECT  0 42.096 0.084 42.12 ;
    END
  END r_q[459]
  PIN r_q[45]
    DIRECTION OUTPUT ;
    USE SIGNAL ;
    PORT
      LAYER M4 ;
        RECT  0 6.96 0.084 6.984 ;
    END
  END r_q[45]
  PIN r_q[460]
    DIRECTION OUTPUT ;
    USE SIGNAL ;
    PORT
      LAYER M4 ;
        RECT  0 42.192 0.084 42.216 ;
    END
  END r_q[460]
  PIN r_q[461]
    DIRECTION OUTPUT ;
    USE SIGNAL ;
    PORT
      LAYER M4 ;
        RECT  0 42.288 0.084 42.312 ;
    END
  END r_q[461]
  PIN r_q[462]
    DIRECTION OUTPUT ;
    USE SIGNAL ;
    PORT
      LAYER M4 ;
        RECT  0 42.384 0.084 42.408 ;
    END
  END r_q[462]
  PIN r_q[463]
    DIRECTION OUTPUT ;
    USE SIGNAL ;
    PORT
      LAYER M4 ;
        RECT  0 42.48 0.084 42.504 ;
    END
  END r_q[463]
  PIN r_q[464]
    DIRECTION OUTPUT ;
    USE SIGNAL ;
    PORT
      LAYER M4 ;
        RECT  0 42.576 0.084 42.6 ;
    END
  END r_q[464]
  PIN r_q[465]
    DIRECTION OUTPUT ;
    USE SIGNAL ;
    PORT
      LAYER M4 ;
        RECT  0 45.744 0.084 45.768 ;
    END
  END r_q[465]
  PIN r_q[466]
    DIRECTION OUTPUT ;
    USE SIGNAL ;
    PORT
      LAYER M4 ;
        RECT  0 45.84 0.084 45.864 ;
    END
  END r_q[466]
  PIN r_q[467]
    DIRECTION OUTPUT ;
    USE SIGNAL ;
    PORT
      LAYER M4 ;
        RECT  0 45.936 0.084 45.96 ;
    END
  END r_q[467]
  PIN r_q[468]
    DIRECTION OUTPUT ;
    USE SIGNAL ;
    PORT
      LAYER M4 ;
        RECT  0 46.032 0.084 46.056 ;
    END
  END r_q[468]
  PIN r_q[469]
    DIRECTION OUTPUT ;
    USE SIGNAL ;
    PORT
      LAYER M4 ;
        RECT  0 46.128 0.084 46.152 ;
    END
  END r_q[469]
  PIN r_q[46]
    DIRECTION OUTPUT ;
    USE SIGNAL ;
    PORT
      LAYER M4 ;
        RECT  0 7.056 0.084 7.08 ;
    END
  END r_q[46]
  PIN r_q[470]
    DIRECTION OUTPUT ;
    USE SIGNAL ;
    PORT
      LAYER M4 ;
        RECT  0 46.224 0.084 46.248 ;
    END
  END r_q[470]
  PIN r_q[471]
    DIRECTION OUTPUT ;
    USE SIGNAL ;
    PORT
      LAYER M4 ;
        RECT  0 46.32 0.084 46.344 ;
    END
  END r_q[471]
  PIN r_q[472]
    DIRECTION OUTPUT ;
    USE SIGNAL ;
    PORT
      LAYER M4 ;
        RECT  0 46.416 0.084 46.44 ;
    END
  END r_q[472]
  PIN r_q[473]
    DIRECTION OUTPUT ;
    USE SIGNAL ;
    PORT
      LAYER M4 ;
        RECT  0 46.512 0.084 46.536 ;
    END
  END r_q[473]
  PIN r_q[474]
    DIRECTION OUTPUT ;
    USE SIGNAL ;
    PORT
      LAYER M4 ;
        RECT  0 46.608 0.084 46.632 ;
    END
  END r_q[474]
  PIN r_q[475]
    DIRECTION OUTPUT ;
    USE SIGNAL ;
    PORT
      LAYER M4 ;
        RECT  0 46.704 0.084 46.728 ;
    END
  END r_q[475]
  PIN r_q[476]
    DIRECTION OUTPUT ;
    USE SIGNAL ;
    PORT
      LAYER M4 ;
        RECT  0 46.8 0.084 46.824 ;
    END
  END r_q[476]
  PIN r_q[477]
    DIRECTION OUTPUT ;
    USE SIGNAL ;
    PORT
      LAYER M4 ;
        RECT  0 46.896 0.084 46.92 ;
    END
  END r_q[477]
  PIN r_q[478]
    DIRECTION OUTPUT ;
    USE SIGNAL ;
    PORT
      LAYER M4 ;
        RECT  0 46.992 0.084 47.016 ;
    END
  END r_q[478]
  PIN r_q[479]
    DIRECTION OUTPUT ;
    USE SIGNAL ;
    PORT
      LAYER M4 ;
        RECT  0 47.088 0.084 47.112 ;
    END
  END r_q[479]
  PIN r_q[47]
    DIRECTION OUTPUT ;
    USE SIGNAL ;
    PORT
      LAYER M4 ;
        RECT  0 7.152 0.084 7.176 ;
    END
  END r_q[47]
  PIN r_q[480]
    DIRECTION OUTPUT ;
    USE SIGNAL ;
    PORT
      LAYER M4 ;
        RECT  0 47.184 0.084 47.208 ;
    END
  END r_q[480]
  PIN r_q[481]
    DIRECTION OUTPUT ;
    USE SIGNAL ;
    PORT
      LAYER M4 ;
        RECT  0 47.28 0.084 47.304 ;
    END
  END r_q[481]
  PIN r_q[482]
    DIRECTION OUTPUT ;
    USE SIGNAL ;
    PORT
      LAYER M4 ;
        RECT  0 47.376 0.084 47.4 ;
    END
  END r_q[482]
  PIN r_q[483]
    DIRECTION OUTPUT ;
    USE SIGNAL ;
    PORT
      LAYER M4 ;
        RECT  0 47.472 0.084 47.496 ;
    END
  END r_q[483]
  PIN r_q[484]
    DIRECTION OUTPUT ;
    USE SIGNAL ;
    PORT
      LAYER M4 ;
        RECT  0 47.568 0.084 47.592 ;
    END
  END r_q[484]
  PIN r_q[485]
    DIRECTION OUTPUT ;
    USE SIGNAL ;
    PORT
      LAYER M4 ;
        RECT  0 47.664 0.084 47.688 ;
    END
  END r_q[485]
  PIN r_q[486]
    DIRECTION OUTPUT ;
    USE SIGNAL ;
    PORT
      LAYER M4 ;
        RECT  0 47.76 0.084 47.784 ;
    END
  END r_q[486]
  PIN r_q[487]
    DIRECTION OUTPUT ;
    USE SIGNAL ;
    PORT
      LAYER M4 ;
        RECT  0 47.856 0.084 47.88 ;
    END
  END r_q[487]
  PIN r_q[488]
    DIRECTION OUTPUT ;
    USE SIGNAL ;
    PORT
      LAYER M4 ;
        RECT  0 47.952 0.084 47.976 ;
    END
  END r_q[488]
  PIN r_q[489]
    DIRECTION OUTPUT ;
    USE SIGNAL ;
    PORT
      LAYER M4 ;
        RECT  0 48.048 0.084 48.072 ;
    END
  END r_q[489]
  PIN r_q[48]
    DIRECTION OUTPUT ;
    USE SIGNAL ;
    PORT
      LAYER M4 ;
        RECT  0 7.248 0.084 7.272 ;
    END
  END r_q[48]
  PIN r_q[490]
    DIRECTION OUTPUT ;
    USE SIGNAL ;
    PORT
      LAYER M4 ;
        RECT  0 48.144 0.084 48.168 ;
    END
  END r_q[490]
  PIN r_q[491]
    DIRECTION OUTPUT ;
    USE SIGNAL ;
    PORT
      LAYER M4 ;
        RECT  0 48.24 0.084 48.264 ;
    END
  END r_q[491]
  PIN r_q[492]
    DIRECTION OUTPUT ;
    USE SIGNAL ;
    PORT
      LAYER M4 ;
        RECT  0 48.336 0.084 48.36 ;
    END
  END r_q[492]
  PIN r_q[493]
    DIRECTION OUTPUT ;
    USE SIGNAL ;
    PORT
      LAYER M4 ;
        RECT  0 48.432 0.084 48.456 ;
    END
  END r_q[493]
  PIN r_q[494]
    DIRECTION OUTPUT ;
    USE SIGNAL ;
    PORT
      LAYER M4 ;
        RECT  0 48.528 0.084 48.552 ;
    END
  END r_q[494]
  PIN r_q[495]
    DIRECTION OUTPUT ;
    USE SIGNAL ;
    PORT
      LAYER M4 ;
        RECT  0 48.624 0.084 48.648 ;
    END
  END r_q[495]
  PIN r_q[496]
    DIRECTION OUTPUT ;
    USE SIGNAL ;
    PORT
      LAYER M4 ;
        RECT  0 48.72 0.084 48.744 ;
    END
  END r_q[496]
  PIN r_q[497]
    DIRECTION OUTPUT ;
    USE SIGNAL ;
    PORT
      LAYER M4 ;
        RECT  0 52.656 0.084 52.68 ;
    END
  END r_q[497]
  PIN r_q[498]
    DIRECTION OUTPUT ;
    USE SIGNAL ;
    PORT
      LAYER M4 ;
        RECT  0 52.752 0.084 52.776 ;
    END
  END r_q[498]
  PIN r_q[499]
    DIRECTION OUTPUT ;
    USE SIGNAL ;
    PORT
      LAYER M4 ;
        RECT  0 52.848 0.084 52.872 ;
    END
  END r_q[499]
  PIN r_q[49]
    DIRECTION OUTPUT ;
    USE SIGNAL ;
    PORT
      LAYER M4 ;
        RECT  0 17.328 0.084 17.352 ;
    END
  END r_q[49]
  PIN r_q[4]
    DIRECTION OUTPUT ;
    USE SIGNAL ;
    PORT
      LAYER M4 ;
        RECT  0 22.224 0.084 22.248 ;
    END
  END r_q[4]
  PIN r_q[500]
    DIRECTION OUTPUT ;
    USE SIGNAL ;
    PORT
      LAYER M4 ;
        RECT  0 52.944 0.084 52.968 ;
    END
  END r_q[500]
  PIN r_q[501]
    DIRECTION OUTPUT ;
    USE SIGNAL ;
    PORT
      LAYER M4 ;
        RECT  0 53.04 0.084 53.064 ;
    END
  END r_q[501]
  PIN r_q[502]
    DIRECTION OUTPUT ;
    USE SIGNAL ;
    PORT
      LAYER M4 ;
        RECT  0 53.136 0.084 53.16 ;
    END
  END r_q[502]
  PIN r_q[503]
    DIRECTION OUTPUT ;
    USE SIGNAL ;
    PORT
      LAYER M4 ;
        RECT  0 53.232 0.084 53.256 ;
    END
  END r_q[503]
  PIN r_q[504]
    DIRECTION OUTPUT ;
    USE SIGNAL ;
    PORT
      LAYER M4 ;
        RECT  0 53.328 0.084 53.352 ;
    END
  END r_q[504]
  PIN r_q[505]
    DIRECTION OUTPUT ;
    USE SIGNAL ;
    PORT
      LAYER M4 ;
        RECT  0 53.424 0.084 53.448 ;
    END
  END r_q[505]
  PIN r_q[506]
    DIRECTION OUTPUT ;
    USE SIGNAL ;
    PORT
      LAYER M4 ;
        RECT  0 53.52 0.084 53.544 ;
    END
  END r_q[506]
  PIN r_q[507]
    DIRECTION OUTPUT ;
    USE SIGNAL ;
    PORT
      LAYER M4 ;
        RECT  0 53.616 0.084 53.64 ;
    END
  END r_q[507]
  PIN r_q[508]
    DIRECTION OUTPUT ;
    USE SIGNAL ;
    PORT
      LAYER M4 ;
        RECT  0 53.712 0.084 53.736 ;
    END
  END r_q[508]
  PIN r_q[509]
    DIRECTION OUTPUT ;
    USE SIGNAL ;
    PORT
      LAYER M4 ;
        RECT  0 53.808 0.084 53.832 ;
    END
  END r_q[509]
  PIN r_q[50]
    DIRECTION OUTPUT ;
    USE SIGNAL ;
    PORT
      LAYER M4 ;
        RECT  0 17.424 0.084 17.448 ;
    END
  END r_q[50]
  PIN r_q[510]
    DIRECTION OUTPUT ;
    USE SIGNAL ;
    PORT
      LAYER M4 ;
        RECT  0 53.904 0.084 53.928 ;
    END
  END r_q[510]
  PIN r_q[511]
    DIRECTION OUTPUT ;
    USE SIGNAL ;
    PORT
      LAYER M4 ;
        RECT  0 54 0.084 54.024 ;
    END
  END r_q[511]
  PIN r_q[51]
    DIRECTION OUTPUT ;
    USE SIGNAL ;
    PORT
      LAYER M4 ;
        RECT  0 17.52 0.084 17.544 ;
    END
  END r_q[51]
  PIN r_q[52]
    DIRECTION OUTPUT ;
    USE SIGNAL ;
    PORT
      LAYER M4 ;
        RECT  0 17.616 0.084 17.64 ;
    END
  END r_q[52]
  PIN r_q[53]
    DIRECTION OUTPUT ;
    USE SIGNAL ;
    PORT
      LAYER M4 ;
        RECT  0 17.712 0.084 17.736 ;
    END
  END r_q[53]
  PIN r_q[54]
    DIRECTION OUTPUT ;
    USE SIGNAL ;
    PORT
      LAYER M4 ;
        RECT  0 17.808 0.084 17.832 ;
    END
  END r_q[54]
  PIN r_q[55]
    DIRECTION OUTPUT ;
    USE SIGNAL ;
    PORT
      LAYER M4 ;
        RECT  0 17.904 0.084 17.928 ;
    END
  END r_q[55]
  PIN r_q[56]
    DIRECTION OUTPUT ;
    USE SIGNAL ;
    PORT
      LAYER M4 ;
        RECT  0 18 0.084 18.024 ;
    END
  END r_q[56]
  PIN r_q[57]
    DIRECTION OUTPUT ;
    USE SIGNAL ;
    PORT
      LAYER M4 ;
        RECT  0 18.096 0.084 18.12 ;
    END
  END r_q[57]
  PIN r_q[58]
    DIRECTION OUTPUT ;
    USE SIGNAL ;
    PORT
      LAYER M4 ;
        RECT  0 18.192 0.084 18.216 ;
    END
  END r_q[58]
  PIN r_q[59]
    DIRECTION OUTPUT ;
    USE SIGNAL ;
    PORT
      LAYER M4 ;
        RECT  0 18.288 0.084 18.312 ;
    END
  END r_q[59]
  PIN r_q[5]
    DIRECTION OUTPUT ;
    USE SIGNAL ;
    PORT
      LAYER M4 ;
        RECT  0 22.32 0.084 22.344 ;
    END
  END r_q[5]
  PIN r_q[60]
    DIRECTION OUTPUT ;
    USE SIGNAL ;
    PORT
      LAYER M4 ;
        RECT  0 18.384 0.084 18.408 ;
    END
  END r_q[60]
  PIN r_q[61]
    DIRECTION OUTPUT ;
    USE SIGNAL ;
    PORT
      LAYER M4 ;
        RECT  0 18.48 0.084 18.504 ;
    END
  END r_q[61]
  PIN r_q[62]
    DIRECTION OUTPUT ;
    USE SIGNAL ;
    PORT
      LAYER M4 ;
        RECT  0 18.576 0.084 18.6 ;
    END
  END r_q[62]
  PIN r_q[63]
    DIRECTION OUTPUT ;
    USE SIGNAL ;
    PORT
      LAYER M4 ;
        RECT  0 18.672 0.084 18.696 ;
    END
  END r_q[63]
  PIN r_q[64]
    DIRECTION OUTPUT ;
    USE SIGNAL ;
    PORT
      LAYER M4 ;
        RECT  0 18.768 0.084 18.792 ;
    END
  END r_q[64]
  PIN r_q[65]
    DIRECTION OUTPUT ;
    USE SIGNAL ;
    PORT
      LAYER M4 ;
        RECT  0 18.864 0.084 18.888 ;
    END
  END r_q[65]
  PIN r_q[66]
    DIRECTION OUTPUT ;
    USE SIGNAL ;
    PORT
      LAYER M4 ;
        RECT  0 18.96 0.084 18.984 ;
    END
  END r_q[66]
  PIN r_q[67]
    DIRECTION OUTPUT ;
    USE SIGNAL ;
    PORT
      LAYER M4 ;
        RECT  0 19.056 0.084 19.08 ;
    END
  END r_q[67]
  PIN r_q[68]
    DIRECTION OUTPUT ;
    USE SIGNAL ;
    PORT
      LAYER M4 ;
        RECT  0 19.152 0.084 19.176 ;
    END
  END r_q[68]
  PIN r_q[69]
    DIRECTION OUTPUT ;
    USE SIGNAL ;
    PORT
      LAYER M4 ;
        RECT  0 19.248 0.084 19.272 ;
    END
  END r_q[69]
  PIN r_q[6]
    DIRECTION OUTPUT ;
    USE SIGNAL ;
    PORT
      LAYER M4 ;
        RECT  0 22.416 0.084 22.44 ;
    END
  END r_q[6]
  PIN r_q[70]
    DIRECTION OUTPUT ;
    USE SIGNAL ;
    PORT
      LAYER M4 ;
        RECT  0 19.344 0.084 19.368 ;
    END
  END r_q[70]
  PIN r_q[71]
    DIRECTION OUTPUT ;
    USE SIGNAL ;
    PORT
      LAYER M4 ;
        RECT  0 19.44 0.084 19.464 ;
    END
  END r_q[71]
  PIN r_q[72]
    DIRECTION OUTPUT ;
    USE SIGNAL ;
    PORT
      LAYER M4 ;
        RECT  0 19.536 0.084 19.56 ;
    END
  END r_q[72]
  PIN r_q[73]
    DIRECTION OUTPUT ;
    USE SIGNAL ;
    PORT
      LAYER M4 ;
        RECT  0 19.632 0.084 19.656 ;
    END
  END r_q[73]
  PIN r_q[74]
    DIRECTION OUTPUT ;
    USE SIGNAL ;
    PORT
      LAYER M4 ;
        RECT  0 19.728 0.084 19.752 ;
    END
  END r_q[74]
  PIN r_q[75]
    DIRECTION OUTPUT ;
    USE SIGNAL ;
    PORT
      LAYER M4 ;
        RECT  0 19.824 0.084 19.848 ;
    END
  END r_q[75]
  PIN r_q[76]
    DIRECTION OUTPUT ;
    USE SIGNAL ;
    PORT
      LAYER M4 ;
        RECT  0 19.92 0.084 19.944 ;
    END
  END r_q[76]
  PIN r_q[77]
    DIRECTION OUTPUT ;
    USE SIGNAL ;
    PORT
      LAYER M4 ;
        RECT  0 20.016 0.084 20.04 ;
    END
  END r_q[77]
  PIN r_q[78]
    DIRECTION OUTPUT ;
    USE SIGNAL ;
    PORT
      LAYER M4 ;
        RECT  0 20.112 0.084 20.136 ;
    END
  END r_q[78]
  PIN r_q[79]
    DIRECTION OUTPUT ;
    USE SIGNAL ;
    PORT
      LAYER M4 ;
        RECT  0 20.208 0.084 20.232 ;
    END
  END r_q[79]
  PIN r_q[7]
    DIRECTION OUTPUT ;
    USE SIGNAL ;
    PORT
      LAYER M4 ;
        RECT  0 22.512 0.084 22.536 ;
    END
  END r_q[7]
  PIN r_q[80]
    DIRECTION OUTPUT ;
    USE SIGNAL ;
    PORT
      LAYER M4 ;
        RECT  0 20.304 0.084 20.328 ;
    END
  END r_q[80]
  PIN r_q[81]
    DIRECTION OUTPUT ;
    USE SIGNAL ;
    PORT
      LAYER M4 ;
        RECT  0 14.256 0.084 14.28 ;
    END
  END r_q[81]
  PIN r_q[82]
    DIRECTION OUTPUT ;
    USE SIGNAL ;
    PORT
      LAYER M4 ;
        RECT  0 14.352 0.084 14.376 ;
    END
  END r_q[82]
  PIN r_q[83]
    DIRECTION OUTPUT ;
    USE SIGNAL ;
    PORT
      LAYER M4 ;
        RECT  0 14.448 0.084 14.472 ;
    END
  END r_q[83]
  PIN r_q[84]
    DIRECTION OUTPUT ;
    USE SIGNAL ;
    PORT
      LAYER M4 ;
        RECT  0 14.544 0.084 14.568 ;
    END
  END r_q[84]
  PIN r_q[85]
    DIRECTION OUTPUT ;
    USE SIGNAL ;
    PORT
      LAYER M4 ;
        RECT  0 14.64 0.084 14.664 ;
    END
  END r_q[85]
  PIN r_q[86]
    DIRECTION OUTPUT ;
    USE SIGNAL ;
    PORT
      LAYER M4 ;
        RECT  0 14.736 0.084 14.76 ;
    END
  END r_q[86]
  PIN r_q[87]
    DIRECTION OUTPUT ;
    USE SIGNAL ;
    PORT
      LAYER M4 ;
        RECT  0 14.832 0.084 14.856 ;
    END
  END r_q[87]
  PIN r_q[88]
    DIRECTION OUTPUT ;
    USE SIGNAL ;
    PORT
      LAYER M4 ;
        RECT  0 14.928 0.084 14.952 ;
    END
  END r_q[88]
  PIN r_q[89]
    DIRECTION OUTPUT ;
    USE SIGNAL ;
    PORT
      LAYER M4 ;
        RECT  0 15.024 0.084 15.048 ;
    END
  END r_q[89]
  PIN r_q[8]
    DIRECTION OUTPUT ;
    USE SIGNAL ;
    PORT
      LAYER M4 ;
        RECT  0 22.608 0.084 22.632 ;
    END
  END r_q[8]
  PIN r_q[90]
    DIRECTION OUTPUT ;
    USE SIGNAL ;
    PORT
      LAYER M4 ;
        RECT  0 15.12 0.084 15.144 ;
    END
  END r_q[90]
  PIN r_q[91]
    DIRECTION OUTPUT ;
    USE SIGNAL ;
    PORT
      LAYER M4 ;
        RECT  0 15.216 0.084 15.24 ;
    END
  END r_q[91]
  PIN r_q[92]
    DIRECTION OUTPUT ;
    USE SIGNAL ;
    PORT
      LAYER M4 ;
        RECT  0 15.312 0.084 15.336 ;
    END
  END r_q[92]
  PIN r_q[93]
    DIRECTION OUTPUT ;
    USE SIGNAL ;
    PORT
      LAYER M4 ;
        RECT  0 15.408 0.084 15.432 ;
    END
  END r_q[93]
  PIN r_q[94]
    DIRECTION OUTPUT ;
    USE SIGNAL ;
    PORT
      LAYER M4 ;
        RECT  0 15.504 0.084 15.528 ;
    END
  END r_q[94]
  PIN r_q[95]
    DIRECTION OUTPUT ;
    USE SIGNAL ;
    PORT
      LAYER M4 ;
        RECT  0 15.6 0.084 15.624 ;
    END
  END r_q[95]
  PIN r_q[96]
    DIRECTION OUTPUT ;
    USE SIGNAL ;
    PORT
      LAYER M4 ;
        RECT  0 15.696 0.084 15.72 ;
    END
  END r_q[96]
  PIN r_q[97]
    DIRECTION OUTPUT ;
    USE SIGNAL ;
    PORT
      LAYER M4 ;
        RECT  0 15.792 0.084 15.816 ;
    END
  END r_q[97]
  PIN r_q[98]
    DIRECTION OUTPUT ;
    USE SIGNAL ;
    PORT
      LAYER M4 ;
        RECT  0 15.888 0.084 15.912 ;
    END
  END r_q[98]
  PIN r_q[99]
    DIRECTION OUTPUT ;
    USE SIGNAL ;
    PORT
      LAYER M4 ;
        RECT  0 15.984 0.084 16.008 ;
    END
  END r_q[99]
  PIN r_q[9]
    DIRECTION OUTPUT ;
    USE SIGNAL ;
    PORT
      LAYER M4 ;
        RECT  0 22.704 0.084 22.728 ;
    END
  END r_q[9]
  PIN rst_n
    DIRECTION INPUT ;
    USE SIGNAL ;
    PORT
      LAYER M4 ;
        RECT  0 54.096 0.084 54.12 ;
    END
  END rst_n
  PIN VSS
    DIRECTION INOUT ;
    USE GROUND ;
    PORT
      LAYER M5 ;
        RECT  166.164 4.297 166.284 105.863 ;
        RECT  161.844 4.297 161.964 105.863 ;
        RECT  157.524 4.297 157.644 105.863 ;
        RECT  153.204 4.297 153.324 105.863 ;
        RECT  148.884 4.297 149.004 105.863 ;
        RECT  144.564 4.297 144.684 105.863 ;
        RECT  140.244 4.297 140.364 105.863 ;
        RECT  135.924 4.297 136.044 105.863 ;
        RECT  131.604 4.297 131.724 105.863 ;
        RECT  127.284 4.297 127.404 105.863 ;
        RECT  122.964 4.297 123.084 105.863 ;
        RECT  118.644 4.297 118.764 105.863 ;
        RECT  114.324 4.297 114.444 105.863 ;
        RECT  110.004 4.297 110.124 105.863 ;
        RECT  105.684 4.297 105.804 105.863 ;
        RECT  101.364 4.297 101.484 105.863 ;
        RECT  97.044 4.297 97.164 105.863 ;
        RECT  92.724 4.297 92.844 105.863 ;
        RECT  88.404 4.297 88.524 105.863 ;
        RECT  84.084 4.297 84.204 105.863 ;
        RECT  79.764 4.297 79.884 105.863 ;
        RECT  75.444 4.297 75.564 105.863 ;
        RECT  71.124 4.297 71.244 105.863 ;
        RECT  66.804 4.297 66.924 105.863 ;
        RECT  62.484 4.297 62.604 105.863 ;
        RECT  58.164 4.297 58.284 105.863 ;
        RECT  53.844 4.297 53.964 105.863 ;
        RECT  49.524 4.297 49.644 105.863 ;
        RECT  45.204 4.297 45.324 105.863 ;
        RECT  40.884 4.297 41.004 105.863 ;
        RECT  36.564 4.297 36.684 105.863 ;
        RECT  32.244 4.297 32.364 105.863 ;
        RECT  27.924 4.297 28.044 105.863 ;
        RECT  23.604 4.297 23.724 105.863 ;
        RECT  19.284 4.297 19.404 105.863 ;
        RECT  14.964 4.297 15.084 105.863 ;
        RECT  10.644 4.297 10.764 105.863 ;
        RECT  6.324 4.297 6.444 105.863 ;
    END
  END VSS
  PIN VDD
    DIRECTION INOUT ;
    USE POWER ;
    PORT
      LAYER M5 ;
        RECT  166.356 4.311 166.476 105.849 ;
        RECT  162.036 4.311 162.156 105.849 ;
        RECT  157.716 4.311 157.836 105.849 ;
        RECT  153.396 4.311 153.516 105.849 ;
        RECT  149.076 4.311 149.196 105.849 ;
        RECT  144.756 4.311 144.876 105.849 ;
        RECT  140.436 4.311 140.556 105.849 ;
        RECT  136.116 4.311 136.236 105.849 ;
        RECT  131.796 4.311 131.916 105.849 ;
        RECT  127.476 4.311 127.596 105.849 ;
        RECT  123.156 4.311 123.276 105.849 ;
        RECT  118.836 4.311 118.956 105.849 ;
        RECT  114.516 4.311 114.636 105.849 ;
        RECT  110.196 4.311 110.316 105.849 ;
        RECT  105.876 4.311 105.996 105.849 ;
        RECT  101.556 4.311 101.676 105.849 ;
        RECT  97.236 4.311 97.356 105.849 ;
        RECT  92.916 4.311 93.036 105.849 ;
        RECT  88.596 4.311 88.716 105.849 ;
        RECT  84.276 4.311 84.396 105.849 ;
        RECT  79.956 4.311 80.076 105.849 ;
        RECT  75.636 4.311 75.756 105.849 ;
        RECT  71.316 4.311 71.436 105.849 ;
        RECT  66.996 4.311 67.116 105.849 ;
        RECT  62.676 4.311 62.796 105.849 ;
        RECT  58.356 4.311 58.476 105.849 ;
        RECT  54.036 4.311 54.156 105.849 ;
        RECT  49.716 4.311 49.836 105.849 ;
        RECT  45.396 4.311 45.516 105.849 ;
        RECT  41.076 4.311 41.196 105.849 ;
        RECT  36.756 4.311 36.876 105.849 ;
        RECT  32.436 4.311 32.556 105.849 ;
        RECT  28.116 4.311 28.236 105.849 ;
        RECT  23.796 4.311 23.916 105.849 ;
        RECT  19.476 4.311 19.596 105.849 ;
        RECT  15.156 4.311 15.276 105.849 ;
        RECT  10.836 4.311 10.956 105.849 ;
        RECT  6.516 4.311 6.636 105.849 ;
    END
  END VDD
  OBS
    LAYER RVTN ;
     RECT  0 1.195 168.48 105.863 ;
    LAYER RVTP ;
     RECT  0 1.195 168.48 105.863 ;
    LAYER M1 ;
     RECT  0 1.195 168.48 105.863 ;
    LAYER M2 ;
     RECT  0 1.195 168.48 105.863 ;
    LAYER M3 ;
     RECT  0 1.195 168.48 105.863 ;
    LAYER M4 ;
     RECT  0 1.195 168.48 105.863 ;
    LAYER M5 ;
     RECT  0 1.195 168.48 105.863 ;
  END
END ot_qwen_tile_romleaf
END LIBRARY
